VERSION 5.7 ;
  NOWIREEXTENSIONATPIN ON ;
  DIVIDERCHAR "/" ;
  BUSBITCHARS "[]" ;
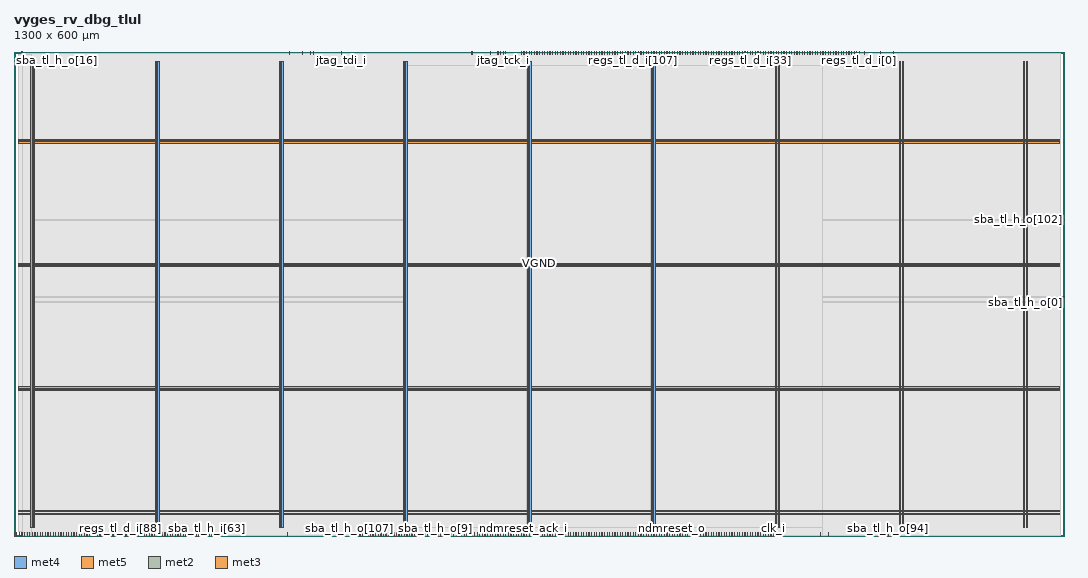
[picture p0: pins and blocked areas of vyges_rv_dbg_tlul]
MACRO vyges_rv_dbg_tlul
  CLASS BLOCK ;
  FOREIGN vyges_rv_dbg_tlul ;
  ORIGIN 0.000 0.000 ;
  SIZE 1300.000 BY 600.000 ;
  PIN VGND
    DIRECTION INOUT ;
    USE GROUND ;
    PORT
      LAYER met4 ;
        RECT 24.340 10.640 25.940 587.760 ;
    END
    PORT
      LAYER met4 ;
        RECT 177.940 10.640 179.540 587.760 ;
    END
    PORT
      LAYER met4 ;
        RECT 331.540 10.640 333.140 587.760 ;
    END
    PORT
      LAYER met4 ;
        RECT 485.140 10.640 486.740 587.760 ;
    END
    PORT
      LAYER met4 ;
        RECT 638.740 10.640 640.340 587.760 ;
    END
    PORT
      LAYER met4 ;
        RECT 792.340 10.640 793.940 587.760 ;
    END
    PORT
      LAYER met4 ;
        RECT 945.940 10.640 947.540 587.760 ;
    END
    PORT
      LAYER met4 ;
        RECT 1099.540 10.640 1101.140 587.760 ;
    END
    PORT
      LAYER met4 ;
        RECT 1253.140 10.640 1254.740 587.760 ;
    END
    PORT
      LAYER met5 ;
        RECT 5.280 30.030 1294.680 31.630 ;
    END
    PORT
      LAYER met5 ;
        RECT 5.280 183.210 1294.680 184.810 ;
    END
    PORT
      LAYER met5 ;
        RECT 5.280 336.390 1294.680 337.990 ;
    END
    PORT
      LAYER met5 ;
        RECT 5.280 489.570 1294.680 491.170 ;
    END
  END VGND
  PIN VPWR
    DIRECTION INOUT ;
    USE POWER ;
    PORT
      LAYER met4 ;
        RECT 21.040 10.640 22.640 587.760 ;
    END
    PORT
      LAYER met4 ;
        RECT 174.640 10.640 176.240 587.760 ;
    END
    PORT
      LAYER met4 ;
        RECT 328.240 10.640 329.840 587.760 ;
    END
    PORT
      LAYER met4 ;
        RECT 481.840 10.640 483.440 587.760 ;
    END
    PORT
      LAYER met4 ;
        RECT 635.440 10.640 637.040 587.760 ;
    END
    PORT
      LAYER met4 ;
        RECT 789.040 10.640 790.640 587.760 ;
    END
    PORT
      LAYER met4 ;
        RECT 942.640 10.640 944.240 587.760 ;
    END
    PORT
      LAYER met4 ;
        RECT 1096.240 10.640 1097.840 587.760 ;
    END
    PORT
      LAYER met4 ;
        RECT 1249.840 10.640 1251.440 587.760 ;
    END
    PORT
      LAYER met5 ;
        RECT 5.280 26.730 1294.680 28.330 ;
    END
    PORT
      LAYER met5 ;
        RECT 5.280 179.910 1294.680 181.510 ;
    END
    PORT
      LAYER met5 ;
        RECT 5.280 333.090 1294.680 334.690 ;
    END
    PORT
      LAYER met5 ;
        RECT 5.280 486.270 1294.680 487.870 ;
    END
  END VPWR
  PIN clk_i
    DIRECTION INPUT ;
    USE SIGNAL ;
    ANTENNAGATEAREA 1.286700 ;
    ANTENNADIFFAREA 0.434700 ;
    PORT
      LAYER met2 ;
        RECT 940.330 0.000 940.610 4.000 ;
    END
  END clk_i
  PIN debug_req_o
    DIRECTION OUTPUT ;
    USE SIGNAL ;
    ANTENNADIFFAREA 0.445500 ;
    PORT
      LAYER met2 ;
        RECT 914.570 0.000 914.850 4.000 ;
    END
  END debug_req_o
  PIN dmactive_o
    DIRECTION OUTPUT ;
    USE SIGNAL ;
    ANTENNADIFFAREA 0.445500 ;
    PORT
      LAYER met2 ;
        RECT 917.790 0.000 918.070 4.000 ;
    END
  END dmactive_o
  PIN jtag_tck_i
    DIRECTION INPUT ;
    USE SIGNAL ;
    ANTENNAGATEAREA 0.631200 ;
    ANTENNADIFFAREA 0.434700 ;
    PORT
      LAYER met2 ;
        RECT 605.450 596.000 605.730 600.000 ;
    END
  END jtag_tck_i
  PIN jtag_tdi_i
    DIRECTION INPUT ;
    USE SIGNAL ;
    ANTENNAGATEAREA 0.647700 ;
    ANTENNADIFFAREA 0.434700 ;
    PORT
      LAYER met2 ;
        RECT 405.810 596.000 406.090 600.000 ;
    END
  END jtag_tdi_i
  PIN jtag_tdo_o
    DIRECTION OUTPUT ;
    USE SIGNAL ;
    ANTENNADIFFAREA 0.445500 ;
    PORT
      LAYER met2 ;
        RECT 370.390 596.000 370.670 600.000 ;
    END
  END jtag_tdo_o
  PIN jtag_tdo_oe_o
    DIRECTION OUTPUT ;
    USE SIGNAL ;
    ANTENNADIFFAREA 0.445500 ;
    PORT
      LAYER met2 ;
        RECT 367.170 596.000 367.450 600.000 ;
    END
  END jtag_tdo_oe_o
  PIN jtag_tms_i
    DIRECTION INPUT ;
    USE SIGNAL ;
    ANTENNAGATEAREA 0.647700 ;
    ANTENNADIFFAREA 0.434700 ;
    PORT
      LAYER met2 ;
        RECT 341.410 596.000 341.690 600.000 ;
    END
  END jtag_tms_i
  PIN jtag_trst_ni
    DIRECTION INPUT ;
    USE SIGNAL ;
    ANTENNAGATEAREA 0.631200 ;
    ANTENNADIFFAREA 0.434700 ;
    PORT
      LAYER met2 ;
        RECT 602.230 596.000 602.510 600.000 ;
    END
  END jtag_trst_ni
  PIN ndmreset_ack_i
    DIRECTION INPUT ;
    USE SIGNAL ;
    ANTENNAGATEAREA 0.647700 ;
    ANTENNADIFFAREA 0.434700 ;
    PORT
      LAYER met2 ;
        RECT 631.210 0.000 631.490 4.000 ;
    END
  END ndmreset_ack_i
  PIN ndmreset_o
    DIRECTION OUTPUT ;
    USE SIGNAL ;
    ANTENNADIFFAREA 0.445500 ;
    PORT
      LAYER met2 ;
        RECT 814.750 0.000 815.030 4.000 ;
    END
  END ndmreset_o
  PIN next_dm_addr_i[0]
    DIRECTION INPUT ;
    USE SIGNAL ;
    ANTENNAGATEAREA 0.560700 ;
    ANTENNADIFFAREA 0.434700 ;
    PORT
      LAYER met2 ;
        RECT 708.490 0.000 708.770 4.000 ;
    END
  END next_dm_addr_i[0]
  PIN next_dm_addr_i[10]
    DIRECTION INPUT ;
    USE SIGNAL ;
    ANTENNAGATEAREA 0.560700 ;
    ANTENNADIFFAREA 0.434700 ;
    PORT
      LAYER met2 ;
        RECT 689.170 0.000 689.450 4.000 ;
    END
  END next_dm_addr_i[10]
  PIN next_dm_addr_i[11]
    DIRECTION INPUT ;
    USE SIGNAL ;
    ANTENNAGATEAREA 0.647700 ;
    ANTENNADIFFAREA 0.434700 ;
    PORT
      LAYER met2 ;
        RECT 753.570 0.000 753.850 4.000 ;
    END
  END next_dm_addr_i[11]
  PIN next_dm_addr_i[12]
    DIRECTION INPUT ;
    USE SIGNAL ;
    ANTENNAGATEAREA 0.560700 ;
    ANTENNADIFFAREA 0.434700 ;
    PORT
      LAYER met2 ;
        RECT 702.050 0.000 702.330 4.000 ;
    END
  END next_dm_addr_i[12]
  PIN next_dm_addr_i[13]
    DIRECTION INPUT ;
    USE SIGNAL ;
    ANTENNAGATEAREA 0.647700 ;
    ANTENNADIFFAREA 0.434700 ;
    PORT
      LAYER met2 ;
        RECT 714.930 0.000 715.210 4.000 ;
    END
  END next_dm_addr_i[13]
  PIN next_dm_addr_i[14]
    DIRECTION INPUT ;
    USE SIGNAL ;
    ANTENNAGATEAREA 0.593700 ;
    ANTENNADIFFAREA 0.434700 ;
    PORT
      LAYER met2 ;
        RECT 627.990 596.000 628.270 600.000 ;
    END
  END next_dm_addr_i[14]
  PIN next_dm_addr_i[15]
    DIRECTION INPUT ;
    USE SIGNAL ;
    ANTENNAGATEAREA 0.647700 ;
    ANTENNADIFFAREA 0.434700 ;
    PORT
      LAYER met2 ;
        RECT 599.010 596.000 599.290 600.000 ;
    END
  END next_dm_addr_i[15]
  PIN next_dm_addr_i[16]
    DIRECTION INPUT ;
    USE SIGNAL ;
    ANTENNAGATEAREA 0.631200 ;
    ANTENNADIFFAREA 0.434700 ;
    PORT
      LAYER met2 ;
        RECT 695.610 0.000 695.890 4.000 ;
    END
  END next_dm_addr_i[16]
  PIN next_dm_addr_i[17]
    DIRECTION INPUT ;
    USE SIGNAL ;
    ANTENNAGATEAREA 0.631200 ;
    ANTENNADIFFAREA 0.434700 ;
    PORT
      LAYER met2 ;
        RECT 669.850 0.000 670.130 4.000 ;
    END
  END next_dm_addr_i[17]
  PIN next_dm_addr_i[18]
    DIRECTION INPUT ;
    USE SIGNAL ;
    ANTENNAGATEAREA 0.593700 ;
    ANTENNADIFFAREA 0.434700 ;
    PORT
      LAYER met2 ;
        RECT 937.110 0.000 937.390 4.000 ;
    END
  END next_dm_addr_i[18]
  PIN next_dm_addr_i[19]
    DIRECTION INPUT ;
    USE SIGNAL ;
    ANTENNAGATEAREA 0.647700 ;
    ANTENNADIFFAREA 0.434700 ;
    PORT
      LAYER met2 ;
        RECT 637.650 0.000 637.930 4.000 ;
    END
  END next_dm_addr_i[19]
  PIN next_dm_addr_i[1]
    DIRECTION INPUT ;
    USE SIGNAL ;
    ANTENNAGATEAREA 0.560700 ;
    ANTENNADIFFAREA 0.434700 ;
    PORT
      LAYER met2 ;
        RECT 769.670 0.000 769.950 4.000 ;
    END
  END next_dm_addr_i[1]
  PIN next_dm_addr_i[20]
    DIRECTION INPUT ;
    USE SIGNAL ;
    ANTENNAGATEAREA 0.647700 ;
    ANTENNADIFFAREA 0.434700 ;
    PORT
      LAYER met2 ;
        RECT 599.010 0.000 599.290 4.000 ;
    END
  END next_dm_addr_i[20]
  PIN next_dm_addr_i[21]
    DIRECTION INPUT ;
    USE SIGNAL ;
    ANTENNAGATEAREA 0.647700 ;
    ANTENNADIFFAREA 0.434700 ;
    PORT
      LAYER met2 ;
        RECT 627.990 0.000 628.270 4.000 ;
    END
  END next_dm_addr_i[21]
  PIN next_dm_addr_i[22]
    DIRECTION INPUT ;
    USE SIGNAL ;
    ANTENNAGATEAREA 0.647700 ;
    ANTENNADIFFAREA 0.434700 ;
    PORT
      LAYER met2 ;
        RECT 624.770 0.000 625.050 4.000 ;
    END
  END next_dm_addr_i[22]
  PIN next_dm_addr_i[23]
    DIRECTION INPUT ;
    USE SIGNAL ;
    ANTENNAGATEAREA 0.647700 ;
    ANTENNADIFFAREA 0.434700 ;
    PORT
      LAYER met2 ;
        RECT 621.550 0.000 621.830 4.000 ;
    END
  END next_dm_addr_i[23]
  PIN next_dm_addr_i[24]
    DIRECTION INPUT ;
    USE SIGNAL ;
    ANTENNAGATEAREA 0.647700 ;
    ANTENNADIFFAREA 0.434700 ;
    PORT
      LAYER met2 ;
        RECT 573.250 0.000 573.530 4.000 ;
    END
  END next_dm_addr_i[24]
  PIN next_dm_addr_i[25]
    DIRECTION INPUT ;
    USE SIGNAL ;
    ANTENNAGATEAREA 0.560700 ;
    ANTENNADIFFAREA 0.434700 ;
    PORT
      LAYER met2 ;
        RECT 776.110 0.000 776.390 4.000 ;
    END
  END next_dm_addr_i[25]
  PIN next_dm_addr_i[26]
    DIRECTION INPUT ;
    USE SIGNAL ;
    ANTENNAGATEAREA 0.560700 ;
    ANTENNADIFFAREA 0.434700 ;
    PORT
      LAYER met2 ;
        RECT 801.870 0.000 802.150 4.000 ;
    END
  END next_dm_addr_i[26]
  PIN next_dm_addr_i[27]
    DIRECTION INPUT ;
    USE SIGNAL ;
    ANTENNAGATEAREA 0.647700 ;
    ANTENNADIFFAREA 0.434700 ;
    PORT
      LAYER met2 ;
        RECT 592.570 0.000 592.850 4.000 ;
    END
  END next_dm_addr_i[27]
  PIN next_dm_addr_i[28]
    DIRECTION INPUT ;
    USE SIGNAL ;
    ANTENNAGATEAREA 0.647700 ;
    ANTENNADIFFAREA 0.434700 ;
    PORT
      LAYER met2 ;
        RECT 582.910 0.000 583.190 4.000 ;
    END
  END next_dm_addr_i[28]
  PIN next_dm_addr_i[29]
    DIRECTION INPUT ;
    USE SIGNAL ;
    ANTENNAGATEAREA 0.647700 ;
    ANTENNADIFFAREA 0.434700 ;
    PORT
      LAYER met2 ;
        RECT 644.090 0.000 644.370 4.000 ;
    END
  END next_dm_addr_i[29]
  PIN next_dm_addr_i[2]
    DIRECTION INPUT ;
    USE SIGNAL ;
    ANTENNAGATEAREA 0.647700 ;
    ANTENNADIFFAREA 0.434700 ;
    PORT
      LAYER met2 ;
        RECT 856.610 0.000 856.890 4.000 ;
    END
  END next_dm_addr_i[2]
  PIN next_dm_addr_i[30]
    DIRECTION INPUT ;
    USE SIGNAL ;
    ANTENNAGATEAREA 0.560700 ;
    ANTENNADIFFAREA 0.434700 ;
    PORT
      LAYER met2 ;
        RECT 705.270 0.000 705.550 4.000 ;
    END
  END next_dm_addr_i[30]
  PIN next_dm_addr_i[31]
    DIRECTION INPUT ;
    USE SIGNAL ;
    ANTENNAGATEAREA 0.647700 ;
    ANTENNADIFFAREA 0.434700 ;
    PORT
      LAYER met2 ;
        RECT 666.630 0.000 666.910 4.000 ;
    END
  END next_dm_addr_i[31]
  PIN next_dm_addr_i[3]
    DIRECTION INPUT ;
    USE SIGNAL ;
    ANTENNAGATEAREA 0.593700 ;
    ANTENNADIFFAREA 0.434700 ;
    PORT
      LAYER met2 ;
        RECT 589.350 596.000 589.630 600.000 ;
    END
  END next_dm_addr_i[3]
  PIN next_dm_addr_i[4]
    DIRECTION INPUT ;
    USE SIGNAL ;
    ANTENNAGATEAREA 0.593700 ;
    ANTENNADIFFAREA 0.434700 ;
    PORT
      LAYER met2 ;
        RECT 647.310 596.000 647.590 600.000 ;
    END
  END next_dm_addr_i[4]
  PIN next_dm_addr_i[5]
    DIRECTION INPUT ;
    USE SIGNAL ;
    ANTENNAGATEAREA 0.631200 ;
    ANTENNADIFFAREA 0.434700 ;
    PORT
      LAYER met2 ;
        RECT 805.090 0.000 805.370 4.000 ;
    END
  END next_dm_addr_i[5]
  PIN next_dm_addr_i[6]
    DIRECTION INPUT ;
    USE SIGNAL ;
    ANTENNAGATEAREA 0.647700 ;
    ANTENNADIFFAREA 0.434700 ;
    PORT
      LAYER met2 ;
        RECT 608.670 0.000 608.950 4.000 ;
    END
  END next_dm_addr_i[6]
  PIN next_dm_addr_i[7]
    DIRECTION INPUT ;
    USE SIGNAL ;
    ANTENNAGATEAREA 0.647700 ;
    ANTENNADIFFAREA 0.434700 ;
    PORT
      LAYER met2 ;
        RECT 653.750 0.000 654.030 4.000 ;
    END
  END next_dm_addr_i[7]
  PIN next_dm_addr_i[8]
    DIRECTION INPUT ;
    USE SIGNAL ;
    ANTENNAGATEAREA 0.631200 ;
    ANTENNADIFFAREA 0.434700 ;
    PORT
      LAYER met2 ;
        RECT 727.810 0.000 728.090 4.000 ;
    END
  END next_dm_addr_i[8]
  PIN next_dm_addr_i[9]
    DIRECTION INPUT ;
    USE SIGNAL ;
    ANTENNAGATEAREA 0.593700 ;
    ANTENNADIFFAREA 0.434700 ;
    PORT
      LAYER met2 ;
        RECT 924.230 0.000 924.510 4.000 ;
    END
  END next_dm_addr_i[9]
  PIN regs_tl_d_i[0]
    DIRECTION INPUT ;
    USE SIGNAL ;
    ANTENNAGATEAREA 0.560700 ;
    ANTENNADIFFAREA 0.434700 ;
    PORT
      LAYER met2 ;
        RECT 1046.590 596.000 1046.870 600.000 ;
    END
  END regs_tl_d_i[0]
  PIN regs_tl_d_i[100]
    DIRECTION INPUT ;
    USE SIGNAL ;
    ANTENNAGATEAREA 0.647700 ;
    ANTENNADIFFAREA 0.434700 ;
    PORT
      LAYER met2 ;
        RECT 978.970 596.000 979.250 600.000 ;
    END
  END regs_tl_d_i[100]
  PIN regs_tl_d_i[101]
    DIRECTION INPUT ;
    USE SIGNAL ;
    ANTENNAGATEAREA 0.631200 ;
    ANTENNADIFFAREA 0.434700 ;
    PORT
      LAYER met2 ;
        RECT 689.170 596.000 689.450 600.000 ;
    END
  END regs_tl_d_i[101]
  PIN regs_tl_d_i[102]
    DIRECTION INPUT ;
    USE SIGNAL ;
    ANTENNAGATEAREA 0.631200 ;
    ANTENNADIFFAREA 0.434700 ;
    PORT
      LAYER met2 ;
        RECT 656.970 596.000 657.250 600.000 ;
    END
  END regs_tl_d_i[102]
  PIN regs_tl_d_i[103]
    DIRECTION INPUT ;
    USE SIGNAL ;
    PORT
      LAYER met2 ;
        RECT 0.090 0.000 0.370 4.000 ;
    END
  END regs_tl_d_i[103]
  PIN regs_tl_d_i[104]
    DIRECTION INPUT ;
    USE SIGNAL ;
    PORT
      LAYER met2 ;
        RECT 3.310 0.000 3.590 4.000 ;
    END
  END regs_tl_d_i[104]
  PIN regs_tl_d_i[105]
    DIRECTION INPUT ;
    USE SIGNAL ;
    PORT
      LAYER met2 ;
        RECT 6.530 0.000 6.810 4.000 ;
    END
  END regs_tl_d_i[105]
  PIN regs_tl_d_i[106]
    DIRECTION INPUT ;
    USE SIGNAL ;
    PORT
      LAYER met2 ;
        RECT 9.750 0.000 10.030 4.000 ;
    END
  END regs_tl_d_i[106]
  PIN regs_tl_d_i[107]
    DIRECTION INPUT ;
    USE SIGNAL ;
    ANTENNAGATEAREA 0.631200 ;
    ANTENNADIFFAREA 0.434700 ;
    PORT
      LAYER met2 ;
        RECT 766.450 596.000 766.730 600.000 ;
    END
  END regs_tl_d_i[107]
  PIN regs_tl_d_i[108]
    DIRECTION INPUT ;
    USE SIGNAL ;
    ANTENNAGATEAREA 0.631200 ;
    ANTENNADIFFAREA 0.434700 ;
    PORT
      LAYER met2 ;
        RECT 763.230 596.000 763.510 600.000 ;
    END
  END regs_tl_d_i[108]
  PIN regs_tl_d_i[109]
    DIRECTION INPUT ;
    USE SIGNAL ;
    ANTENNAGATEAREA 0.631200 ;
    ANTENNADIFFAREA 0.434700 ;
    PORT
      LAYER met2 ;
        RECT 917.790 596.000 918.070 600.000 ;
    END
  END regs_tl_d_i[109]
  PIN regs_tl_d_i[10]
    DIRECTION INPUT ;
    USE SIGNAL ;
    PORT
      LAYER met2 ;
        RECT 12.970 0.000 13.250 4.000 ;
    END
  END regs_tl_d_i[10]
  PIN regs_tl_d_i[11]
    DIRECTION INPUT ;
    USE SIGNAL ;
    PORT
      LAYER met2 ;
        RECT 16.190 0.000 16.470 4.000 ;
    END
  END regs_tl_d_i[11]
  PIN regs_tl_d_i[12]
    DIRECTION INPUT ;
    USE SIGNAL ;
    PORT
      LAYER met2 ;
        RECT 19.410 0.000 19.690 4.000 ;
    END
  END regs_tl_d_i[12]
  PIN regs_tl_d_i[13]
    DIRECTION INPUT ;
    USE SIGNAL ;
    PORT
      LAYER met2 ;
        RECT 22.630 0.000 22.910 4.000 ;
    END
  END regs_tl_d_i[13]
  PIN regs_tl_d_i[14]
    DIRECTION INPUT ;
    USE SIGNAL ;
    PORT
      LAYER met2 ;
        RECT 25.850 0.000 26.130 4.000 ;
    END
  END regs_tl_d_i[14]
  PIN regs_tl_d_i[15]
    DIRECTION INPUT ;
    USE SIGNAL ;
    PORT
      LAYER met2 ;
        RECT 29.070 0.000 29.350 4.000 ;
    END
  END regs_tl_d_i[15]
  PIN regs_tl_d_i[16]
    DIRECTION INPUT ;
    USE SIGNAL ;
    PORT
      LAYER met2 ;
        RECT 32.290 0.000 32.570 4.000 ;
    END
  END regs_tl_d_i[16]
  PIN regs_tl_d_i[17]
    DIRECTION INPUT ;
    USE SIGNAL ;
    PORT
      LAYER met2 ;
        RECT 35.510 0.000 35.790 4.000 ;
    END
  END regs_tl_d_i[17]
  PIN regs_tl_d_i[18]
    DIRECTION INPUT ;
    USE SIGNAL ;
    PORT
      LAYER met2 ;
        RECT 38.730 0.000 39.010 4.000 ;
    END
  END regs_tl_d_i[18]
  PIN regs_tl_d_i[19]
    DIRECTION INPUT ;
    USE SIGNAL ;
    PORT
      LAYER met2 ;
        RECT 41.950 0.000 42.230 4.000 ;
    END
  END regs_tl_d_i[19]
  PIN regs_tl_d_i[1]
    DIRECTION INPUT ;
    USE SIGNAL ;
    PORT
      LAYER met2 ;
        RECT 45.170 0.000 45.450 4.000 ;
    END
  END regs_tl_d_i[1]
  PIN regs_tl_d_i[20]
    DIRECTION INPUT ;
    USE SIGNAL ;
    PORT
      LAYER met2 ;
        RECT 48.390 0.000 48.670 4.000 ;
    END
  END regs_tl_d_i[20]
  PIN regs_tl_d_i[21]
    DIRECTION INPUT ;
    USE SIGNAL ;
    PORT
      LAYER met2 ;
        RECT 51.610 0.000 51.890 4.000 ;
    END
  END regs_tl_d_i[21]
  PIN regs_tl_d_i[22]
    DIRECTION INPUT ;
    USE SIGNAL ;
    PORT
      LAYER met2 ;
        RECT 54.830 0.000 55.110 4.000 ;
    END
  END regs_tl_d_i[22]
  PIN regs_tl_d_i[23]
    DIRECTION INPUT ;
    USE SIGNAL ;
    PORT
      LAYER met2 ;
        RECT 58.050 0.000 58.330 4.000 ;
    END
  END regs_tl_d_i[23]
  PIN regs_tl_d_i[24]
    DIRECTION INPUT ;
    USE SIGNAL ;
    PORT
      LAYER met2 ;
        RECT 61.270 0.000 61.550 4.000 ;
    END
  END regs_tl_d_i[24]
  PIN regs_tl_d_i[25]
    DIRECTION INPUT ;
    USE SIGNAL ;
    ANTENNAGATEAREA 0.631200 ;
    ANTENNADIFFAREA 0.434700 ;
    PORT
      LAYER met2 ;
        RECT 760.010 596.000 760.290 600.000 ;
    END
  END regs_tl_d_i[25]
  PIN regs_tl_d_i[26]
    DIRECTION INPUT ;
    USE SIGNAL ;
    ANTENNAGATEAREA 0.631200 ;
    ANTENNADIFFAREA 0.434700 ;
    PORT
      LAYER met2 ;
        RECT 1001.510 596.000 1001.790 600.000 ;
    END
  END regs_tl_d_i[26]
  PIN regs_tl_d_i[27]
    DIRECTION INPUT ;
    USE SIGNAL ;
    ANTENNAGATEAREA 0.560700 ;
    ANTENNADIFFAREA 0.434700 ;
    PORT
      LAYER met2 ;
        RECT 998.290 596.000 998.570 600.000 ;
    END
  END regs_tl_d_i[27]
  PIN regs_tl_d_i[28]
    DIRECTION INPUT ;
    USE SIGNAL ;
    ANTENNAGATEAREA 0.631200 ;
    ANTENNADIFFAREA 0.434700 ;
    PORT
      LAYER met2 ;
        RECT 660.190 596.000 660.470 600.000 ;
    END
  END regs_tl_d_i[28]
  PIN regs_tl_d_i[29]
    DIRECTION INPUT ;
    USE SIGNAL ;
    ANTENNAGATEAREA 0.560700 ;
    ANTENNADIFFAREA 0.434700 ;
    PORT
      LAYER met2 ;
        RECT 1036.930 596.000 1037.210 600.000 ;
    END
  END regs_tl_d_i[29]
  PIN regs_tl_d_i[2]
    DIRECTION INPUT ;
    USE SIGNAL ;
    PORT
      LAYER met2 ;
        RECT 64.490 0.000 64.770 4.000 ;
    END
  END regs_tl_d_i[2]
  PIN regs_tl_d_i[30]
    DIRECTION INPUT ;
    USE SIGNAL ;
    ANTENNAGATEAREA 0.631200 ;
    ANTENNADIFFAREA 0.434700 ;
    PORT
      LAYER met2 ;
        RECT 747.130 596.000 747.410 600.000 ;
    END
  END regs_tl_d_i[30]
  PIN regs_tl_d_i[31]
    DIRECTION INPUT ;
    USE SIGNAL ;
    ANTENNAGATEAREA 0.560700 ;
    ANTENNADIFFAREA 0.434700 ;
    PORT
      LAYER met2 ;
        RECT 1030.490 596.000 1030.770 600.000 ;
    END
  END regs_tl_d_i[31]
  PIN regs_tl_d_i[32]
    DIRECTION INPUT ;
    USE SIGNAL ;
    ANTENNAGATEAREA 0.631200 ;
    ANTENNADIFFAREA 0.434700 ;
    PORT
      LAYER met2 ;
        RECT 663.410 596.000 663.690 600.000 ;
    END
  END regs_tl_d_i[32]
  PIN regs_tl_d_i[33]
    DIRECTION INPUT ;
    USE SIGNAL ;
    ANTENNAGATEAREA 0.631200 ;
    ANTENNADIFFAREA 0.434700 ;
    PORT
      LAYER met2 ;
        RECT 911.350 596.000 911.630 600.000 ;
    END
  END regs_tl_d_i[33]
  PIN regs_tl_d_i[34]
    DIRECTION INPUT ;
    USE SIGNAL ;
    ANTENNAGATEAREA 0.631200 ;
    ANTENNADIFFAREA 0.434700 ;
    PORT
      LAYER met2 ;
        RECT 924.230 596.000 924.510 600.000 ;
    END
  END regs_tl_d_i[34]
  PIN regs_tl_d_i[35]
    DIRECTION INPUT ;
    USE SIGNAL ;
    ANTENNAGATEAREA 0.631200 ;
    ANTENNADIFFAREA 0.434700 ;
    PORT
      LAYER met2 ;
        RECT 953.210 596.000 953.490 600.000 ;
    END
  END regs_tl_d_i[35]
  PIN regs_tl_d_i[36]
    DIRECTION INPUT ;
    USE SIGNAL ;
    ANTENNAGATEAREA 0.631200 ;
    ANTENNADIFFAREA 0.434700 ;
    PORT
      LAYER met2 ;
        RECT 921.010 596.000 921.290 600.000 ;
    END
  END regs_tl_d_i[36]
  PIN regs_tl_d_i[37]
    DIRECTION INPUT ;
    USE SIGNAL ;
    ANTENNAGATEAREA 0.631200 ;
    ANTENNADIFFAREA 0.434700 ;
    PORT
      LAYER met2 ;
        RECT 901.690 596.000 901.970 600.000 ;
    END
  END regs_tl_d_i[37]
  PIN regs_tl_d_i[38]
    DIRECTION INPUT ;
    USE SIGNAL ;
    ANTENNAGATEAREA 0.631200 ;
    ANTENNADIFFAREA 0.434700 ;
    PORT
      LAYER met2 ;
        RECT 827.630 596.000 827.910 600.000 ;
    END
  END regs_tl_d_i[38]
  PIN regs_tl_d_i[39]
    DIRECTION INPUT ;
    USE SIGNAL ;
    ANTENNAGATEAREA 0.631200 ;
    ANTENNADIFFAREA 0.434700 ;
    PORT
      LAYER met2 ;
        RECT 1027.270 596.000 1027.550 600.000 ;
    END
  END regs_tl_d_i[39]
  PIN regs_tl_d_i[3]
    DIRECTION INPUT ;
    USE SIGNAL ;
    PORT
      LAYER met2 ;
        RECT 67.710 0.000 67.990 4.000 ;
    END
  END regs_tl_d_i[3]
  PIN regs_tl_d_i[40]
    DIRECTION INPUT ;
    USE SIGNAL ;
    ANTENNAGATEAREA 0.631200 ;
    ANTENNADIFFAREA 0.434700 ;
    PORT
      LAYER met2 ;
        RECT 685.950 596.000 686.230 600.000 ;
    END
  END regs_tl_d_i[40]
  PIN regs_tl_d_i[41]
    DIRECTION INPUT ;
    USE SIGNAL ;
    ANTENNAGATEAREA 0.631200 ;
    ANTENNADIFFAREA 0.434700 ;
    PORT
      LAYER met2 ;
        RECT 702.050 596.000 702.330 600.000 ;
    END
  END regs_tl_d_i[41]
  PIN regs_tl_d_i[42]
    DIRECTION INPUT ;
    USE SIGNAL ;
    ANTENNAGATEAREA 0.631200 ;
    ANTENNADIFFAREA 0.434700 ;
    PORT
      LAYER met2 ;
        RECT 631.210 596.000 631.490 600.000 ;
    END
  END regs_tl_d_i[42]
  PIN regs_tl_d_i[43]
    DIRECTION INPUT ;
    USE SIGNAL ;
    ANTENNAGATEAREA 0.631200 ;
    ANTENNADIFFAREA 0.434700 ;
    PORT
      LAYER met2 ;
        RECT 975.750 596.000 976.030 600.000 ;
    END
  END regs_tl_d_i[43]
  PIN regs_tl_d_i[44]
    DIRECTION INPUT ;
    USE SIGNAL ;
    ANTENNAGATEAREA 0.631200 ;
    ANTENNADIFFAREA 0.434700 ;
    PORT
      LAYER met2 ;
        RECT 650.530 596.000 650.810 600.000 ;
    END
  END regs_tl_d_i[44]
  PIN regs_tl_d_i[45]
    DIRECTION INPUT ;
    USE SIGNAL ;
    ANTENNAGATEAREA 0.631200 ;
    ANTENNADIFFAREA 0.434700 ;
    PORT
      LAYER met2 ;
        RECT 985.410 596.000 985.690 600.000 ;
    END
  END regs_tl_d_i[45]
  PIN regs_tl_d_i[46]
    DIRECTION INPUT ;
    USE SIGNAL ;
    ANTENNAGATEAREA 0.631200 ;
    ANTENNADIFFAREA 0.434700 ;
    PORT
      LAYER met2 ;
        RECT 779.330 596.000 779.610 600.000 ;
    END
  END regs_tl_d_i[46]
  PIN regs_tl_d_i[47]
    DIRECTION INPUT ;
    USE SIGNAL ;
    ANTENNAGATEAREA 0.631200 ;
    ANTENNADIFFAREA 0.434700 ;
    PORT
      LAYER met2 ;
        RECT 769.670 596.000 769.950 600.000 ;
    END
  END regs_tl_d_i[47]
  PIN regs_tl_d_i[48]
    DIRECTION INPUT ;
    USE SIGNAL ;
    ANTENNAGATEAREA 0.631200 ;
    ANTENNADIFFAREA 0.434700 ;
    PORT
      LAYER met2 ;
        RECT 743.910 596.000 744.190 600.000 ;
    END
  END regs_tl_d_i[48]
  PIN regs_tl_d_i[49]
    DIRECTION INPUT ;
    USE SIGNAL ;
    ANTENNAGATEAREA 0.631200 ;
    ANTENNADIFFAREA 0.434700 ;
    PORT
      LAYER met2 ;
        RECT 653.750 596.000 654.030 600.000 ;
    END
  END regs_tl_d_i[49]
  PIN regs_tl_d_i[4]
    DIRECTION INPUT ;
    USE SIGNAL ;
    PORT
      LAYER met2 ;
        RECT 70.930 0.000 71.210 4.000 ;
    END
  END regs_tl_d_i[4]
  PIN regs_tl_d_i[50]
    DIRECTION INPUT ;
    USE SIGNAL ;
    ANTENNAGATEAREA 0.631200 ;
    ANTENNADIFFAREA 0.434700 ;
    PORT
      LAYER met2 ;
        RECT 1011.170 596.000 1011.450 600.000 ;
    END
  END regs_tl_d_i[50]
  PIN regs_tl_d_i[51]
    DIRECTION INPUT ;
    USE SIGNAL ;
    ANTENNAGATEAREA 0.631200 ;
    ANTENNADIFFAREA 0.434700 ;
    PORT
      LAYER met2 ;
        RECT 1014.390 596.000 1014.670 600.000 ;
    END
  END regs_tl_d_i[51]
  PIN regs_tl_d_i[52]
    DIRECTION INPUT ;
    USE SIGNAL ;
    ANTENNAGATEAREA 0.631200 ;
    ANTENNADIFFAREA 0.434700 ;
    PORT
      LAYER met2 ;
        RECT 640.870 596.000 641.150 600.000 ;
    END
  END regs_tl_d_i[52]
  PIN regs_tl_d_i[53]
    DIRECTION INPUT ;
    USE SIGNAL ;
    ANTENNAGATEAREA 0.631200 ;
    ANTENNADIFFAREA 0.434700 ;
    PORT
      LAYER met2 ;
        RECT 634.430 596.000 634.710 600.000 ;
    END
  END regs_tl_d_i[53]
  PIN regs_tl_d_i[54]
    DIRECTION INPUT ;
    USE SIGNAL ;
    ANTENNAGATEAREA 0.631200 ;
    ANTENNADIFFAREA 0.434700 ;
    PORT
      LAYER met2 ;
        RECT 644.090 596.000 644.370 600.000 ;
    END
  END regs_tl_d_i[54]
  PIN regs_tl_d_i[55]
    DIRECTION INPUT ;
    USE SIGNAL ;
    ANTENNAGATEAREA 0.631200 ;
    ANTENNADIFFAREA 0.434700 ;
    PORT
      LAYER met2 ;
        RECT 676.290 596.000 676.570 600.000 ;
    END
  END regs_tl_d_i[55]
  PIN regs_tl_d_i[56]
    DIRECTION INPUT ;
    USE SIGNAL ;
    ANTENNAGATEAREA 0.631200 ;
    ANTENNADIFFAREA 0.434700 ;
    PORT
      LAYER met2 ;
        RECT 698.830 596.000 699.110 600.000 ;
    END
  END regs_tl_d_i[56]
  PIN regs_tl_d_i[57]
    DIRECTION INPUT ;
    USE SIGNAL ;
    ANTENNAGATEAREA 0.631200 ;
    ANTENNADIFFAREA 0.434700 ;
    PORT
      LAYER met2 ;
        RECT 1017.610 596.000 1017.890 600.000 ;
    END
  END regs_tl_d_i[57]
  PIN regs_tl_d_i[58]
    DIRECTION INPUT ;
    USE SIGNAL ;
    ANTENNAGATEAREA 0.631200 ;
    ANTENNADIFFAREA 0.434700 ;
    PORT
      LAYER met2 ;
        RECT 711.710 596.000 711.990 600.000 ;
    END
  END regs_tl_d_i[58]
  PIN regs_tl_d_i[59]
    DIRECTION INPUT ;
    USE SIGNAL ;
    ANTENNAGATEAREA 0.631200 ;
    ANTENNADIFFAREA 0.434700 ;
    PORT
      LAYER met2 ;
        RECT 1007.950 596.000 1008.230 600.000 ;
    END
  END regs_tl_d_i[59]
  PIN regs_tl_d_i[5]
    DIRECTION INPUT ;
    USE SIGNAL ;
    PORT
      LAYER met2 ;
        RECT 74.150 0.000 74.430 4.000 ;
    END
  END regs_tl_d_i[5]
  PIN regs_tl_d_i[60]
    DIRECTION INPUT ;
    USE SIGNAL ;
    ANTENNAGATEAREA 0.647700 ;
    ANTENNADIFFAREA 0.434700 ;
    PORT
      LAYER met2 ;
        RECT 1024.050 596.000 1024.330 600.000 ;
    END
  END regs_tl_d_i[60]
  PIN regs_tl_d_i[61]
    DIRECTION INPUT ;
    USE SIGNAL ;
    ANTENNAGATEAREA 0.631200 ;
    ANTENNADIFFAREA 0.434700 ;
    PORT
      LAYER met2 ;
        RECT 734.250 596.000 734.530 600.000 ;
    END
  END regs_tl_d_i[61]
  PIN regs_tl_d_i[62]
    DIRECTION INPUT ;
    USE SIGNAL ;
    ANTENNAGATEAREA 0.631200 ;
    ANTENNADIFFAREA 0.434700 ;
    PORT
      LAYER met2 ;
        RECT 988.630 596.000 988.910 600.000 ;
    END
  END regs_tl_d_i[62]
  PIN regs_tl_d_i[63]
    DIRECTION INPUT ;
    USE SIGNAL ;
    ANTENNAGATEAREA 0.631200 ;
    ANTENNADIFFAREA 0.434700 ;
    PORT
      LAYER met2 ;
        RECT 753.570 596.000 753.850 600.000 ;
    END
  END regs_tl_d_i[63]
  PIN regs_tl_d_i[64]
    DIRECTION INPUT ;
    USE SIGNAL ;
    ANTENNAGATEAREA 0.631200 ;
    ANTENNADIFFAREA 0.434700 ;
    PORT
      LAYER met2 ;
        RECT 927.450 596.000 927.730 600.000 ;
    END
  END regs_tl_d_i[64]
  PIN regs_tl_d_i[65]
    DIRECTION INPUT ;
    USE SIGNAL ;
    ANTENNAGATEAREA 0.631200 ;
    ANTENNADIFFAREA 0.434700 ;
    PORT
      LAYER met2 ;
        RECT 637.650 596.000 637.930 600.000 ;
    END
  END regs_tl_d_i[65]
  PIN regs_tl_d_i[66]
    DIRECTION INPUT ;
    USE SIGNAL ;
    ANTENNAGATEAREA 0.631200 ;
    ANTENNADIFFAREA 0.434700 ;
    PORT
      LAYER met2 ;
        RECT 940.330 596.000 940.610 600.000 ;
    END
  END regs_tl_d_i[66]
  PIN regs_tl_d_i[67]
    DIRECTION INPUT ;
    USE SIGNAL ;
    ANTENNAGATEAREA 0.631200 ;
    ANTENNADIFFAREA 0.434700 ;
    PORT
      LAYER met2 ;
        RECT 933.890 596.000 934.170 600.000 ;
    END
  END regs_tl_d_i[67]
  PIN regs_tl_d_i[68]
    DIRECTION INPUT ;
    USE SIGNAL ;
    ANTENNAGATEAREA 0.631200 ;
    ANTENNADIFFAREA 0.434700 ;
    PORT
      LAYER met2 ;
        RECT 962.870 596.000 963.150 600.000 ;
    END
  END regs_tl_d_i[68]
  PIN regs_tl_d_i[69]
    DIRECTION INPUT ;
    USE SIGNAL ;
    ANTENNAGATEAREA 0.631200 ;
    ANTENNADIFFAREA 0.434700 ;
    PORT
      LAYER met2 ;
        RECT 772.890 596.000 773.170 600.000 ;
    END
  END regs_tl_d_i[69]
  PIN regs_tl_d_i[6]
    DIRECTION INPUT ;
    USE SIGNAL ;
    PORT
      LAYER met2 ;
        RECT 77.370 0.000 77.650 4.000 ;
    END
  END regs_tl_d_i[6]
  PIN regs_tl_d_i[70]
    DIRECTION INPUT ;
    USE SIGNAL ;
    ANTENNAGATEAREA 0.631200 ;
    ANTENNADIFFAREA 0.434700 ;
    PORT
      LAYER met2 ;
        RECT 756.790 596.000 757.070 600.000 ;
    END
  END regs_tl_d_i[70]
  PIN regs_tl_d_i[71]
    DIRECTION INPUT ;
    USE SIGNAL ;
    ANTENNAGATEAREA 0.631200 ;
    ANTENNADIFFAREA 0.434700 ;
    PORT
      LAYER met2 ;
        RECT 966.090 596.000 966.370 600.000 ;
    END
  END regs_tl_d_i[71]
  PIN regs_tl_d_i[72]
    DIRECTION INPUT ;
    USE SIGNAL ;
    ANTENNAGATEAREA 0.631200 ;
    ANTENNADIFFAREA 0.434700 ;
    PORT
      LAYER met2 ;
        RECT 959.650 596.000 959.930 600.000 ;
    END
  END regs_tl_d_i[72]
  PIN regs_tl_d_i[73]
    DIRECTION INPUT ;
    USE SIGNAL ;
    PORT
      LAYER met2 ;
        RECT 80.590 0.000 80.870 4.000 ;
    END
  END regs_tl_d_i[73]
  PIN regs_tl_d_i[74]
    DIRECTION INPUT ;
    USE SIGNAL ;
    PORT
      LAYER met2 ;
        RECT 83.810 0.000 84.090 4.000 ;
    END
  END regs_tl_d_i[74]
  PIN regs_tl_d_i[75]
    DIRECTION INPUT ;
    USE SIGNAL ;
    PORT
      LAYER met2 ;
        RECT 87.030 0.000 87.310 4.000 ;
    END
  END regs_tl_d_i[75]
  PIN regs_tl_d_i[76]
    DIRECTION INPUT ;
    USE SIGNAL ;
    PORT
      LAYER met2 ;
        RECT 90.250 0.000 90.530 4.000 ;
    END
  END regs_tl_d_i[76]
  PIN regs_tl_d_i[77]
    DIRECTION INPUT ;
    USE SIGNAL ;
    PORT
      LAYER met2 ;
        RECT 93.470 0.000 93.750 4.000 ;
    END
  END regs_tl_d_i[77]
  PIN regs_tl_d_i[78]
    DIRECTION INPUT ;
    USE SIGNAL ;
    PORT
      LAYER met2 ;
        RECT 96.690 0.000 96.970 4.000 ;
    END
  END regs_tl_d_i[78]
  PIN regs_tl_d_i[79]
    DIRECTION INPUT ;
    USE SIGNAL ;
    PORT
      LAYER met2 ;
        RECT 99.910 0.000 100.190 4.000 ;
    END
  END regs_tl_d_i[79]
  PIN regs_tl_d_i[7]
    DIRECTION INPUT ;
    USE SIGNAL ;
    PORT
      LAYER met2 ;
        RECT 103.130 0.000 103.410 4.000 ;
    END
  END regs_tl_d_i[7]
  PIN regs_tl_d_i[80]
    DIRECTION INPUT ;
    USE SIGNAL ;
    PORT
      LAYER met2 ;
        RECT 106.350 0.000 106.630 4.000 ;
    END
  END regs_tl_d_i[80]
  PIN regs_tl_d_i[81]
    DIRECTION INPUT ;
    USE SIGNAL ;
    PORT
      LAYER met2 ;
        RECT 109.570 0.000 109.850 4.000 ;
    END
  END regs_tl_d_i[81]
  PIN regs_tl_d_i[82]
    DIRECTION INPUT ;
    USE SIGNAL ;
    PORT
      LAYER met2 ;
        RECT 112.790 0.000 113.070 4.000 ;
    END
  END regs_tl_d_i[82]
  PIN regs_tl_d_i[83]
    DIRECTION INPUT ;
    USE SIGNAL ;
    PORT
      LAYER met2 ;
        RECT 116.010 0.000 116.290 4.000 ;
    END
  END regs_tl_d_i[83]
  PIN regs_tl_d_i[84]
    DIRECTION INPUT ;
    USE SIGNAL ;
    PORT
      LAYER met2 ;
        RECT 119.230 0.000 119.510 4.000 ;
    END
  END regs_tl_d_i[84]
  PIN regs_tl_d_i[85]
    DIRECTION INPUT ;
    USE SIGNAL ;
    PORT
      LAYER met2 ;
        RECT 122.450 0.000 122.730 4.000 ;
    END
  END regs_tl_d_i[85]
  PIN regs_tl_d_i[86]
    DIRECTION INPUT ;
    USE SIGNAL ;
    PORT
      LAYER met2 ;
        RECT 125.670 0.000 125.950 4.000 ;
    END
  END regs_tl_d_i[86]
  PIN regs_tl_d_i[87]
    DIRECTION INPUT ;
    USE SIGNAL ;
    PORT
      LAYER met2 ;
        RECT 128.890 0.000 129.170 4.000 ;
    END
  END regs_tl_d_i[87]
  PIN regs_tl_d_i[88]
    DIRECTION INPUT ;
    USE SIGNAL ;
    PORT
      LAYER met2 ;
        RECT 132.110 0.000 132.390 4.000 ;
    END
  END regs_tl_d_i[88]
  PIN regs_tl_d_i[89]
    DIRECTION INPUT ;
    USE SIGNAL ;
    PORT
      LAYER met2 ;
        RECT 135.330 0.000 135.610 4.000 ;
    END
  END regs_tl_d_i[89]
  PIN regs_tl_d_i[8]
    DIRECTION INPUT ;
    USE SIGNAL ;
    PORT
      LAYER met2 ;
        RECT 138.550 0.000 138.830 4.000 ;
    END
  END regs_tl_d_i[8]
  PIN regs_tl_d_i[90]
    DIRECTION INPUT ;
    USE SIGNAL ;
    PORT
      LAYER met2 ;
        RECT 141.770 0.000 142.050 4.000 ;
    END
  END regs_tl_d_i[90]
  PIN regs_tl_d_i[91]
    DIRECTION INPUT ;
    USE SIGNAL ;
    PORT
      LAYER met2 ;
        RECT 144.990 0.000 145.270 4.000 ;
    END
  END regs_tl_d_i[91]
  PIN regs_tl_d_i[92]
    DIRECTION INPUT ;
    USE SIGNAL ;
    PORT
      LAYER met2 ;
        RECT 148.210 0.000 148.490 4.000 ;
    END
  END regs_tl_d_i[92]
  PIN regs_tl_d_i[93]
    DIRECTION INPUT ;
    USE SIGNAL ;
    ANTENNAGATEAREA 0.631200 ;
    ANTENNADIFFAREA 0.434700 ;
    PORT
      LAYER met2 ;
        RECT 995.070 596.000 995.350 600.000 ;
    END
  END regs_tl_d_i[93]
  PIN regs_tl_d_i[94]
    DIRECTION INPUT ;
    USE SIGNAL ;
    ANTENNAGATEAREA 0.647700 ;
    ANTENNADIFFAREA 0.434700 ;
    PORT
      LAYER met2 ;
        RECT 721.370 596.000 721.650 600.000 ;
    END
  END regs_tl_d_i[94]
  PIN regs_tl_d_i[95]
    DIRECTION INPUT ;
    USE SIGNAL ;
    ANTENNAGATEAREA 0.631200 ;
    ANTENNADIFFAREA 0.434700 ;
    PORT
      LAYER met2 ;
        RECT 666.630 596.000 666.910 600.000 ;
    END
  END regs_tl_d_i[95]
  PIN regs_tl_d_i[96]
    DIRECTION INPUT ;
    USE SIGNAL ;
    ANTENNAGATEAREA 0.593700 ;
    ANTENNADIFFAREA 0.434700 ;
    PORT
      LAYER met2 ;
        RECT 1020.830 596.000 1021.110 600.000 ;
    END
  END regs_tl_d_i[96]
  PIN regs_tl_d_i[97]
    DIRECTION INPUT ;
    USE SIGNAL ;
    ANTENNAGATEAREA 0.631200 ;
    ANTENNADIFFAREA 0.434700 ;
    PORT
      LAYER met2 ;
        RECT 724.590 596.000 724.870 600.000 ;
    END
  END regs_tl_d_i[97]
  PIN regs_tl_d_i[98]
    DIRECTION INPUT ;
    USE SIGNAL ;
    ANTENNAGATEAREA 0.631200 ;
    ANTENNADIFFAREA 0.434700 ;
    PORT
      LAYER met2 ;
        RECT 705.270 596.000 705.550 600.000 ;
    END
  END regs_tl_d_i[98]
  PIN regs_tl_d_i[99]
    DIRECTION INPUT ;
    USE SIGNAL ;
    ANTENNAGATEAREA 0.631200 ;
    ANTENNADIFFAREA 0.434700 ;
    PORT
      LAYER met2 ;
        RECT 737.470 596.000 737.750 600.000 ;
    END
  END regs_tl_d_i[99]
  PIN regs_tl_d_i[9]
    DIRECTION INPUT ;
    USE SIGNAL ;
    PORT
      LAYER met2 ;
        RECT 151.430 0.000 151.710 4.000 ;
    END
  END regs_tl_d_i[9]
  PIN regs_tl_d_o[0]
    DIRECTION OUTPUT ;
    USE SIGNAL ;
    ANTENNADIFFAREA 0.445500 ;
    PORT
      LAYER met2 ;
        RECT 908.130 596.000 908.410 600.000 ;
    END
  END regs_tl_d_o[0]
  PIN regs_tl_d_o[10]
    DIRECTION OUTPUT ;
    USE SIGNAL ;
    ANTENNADIFFAREA 0.445500 ;
    PORT
      LAYER met2 ;
        RECT 1043.370 596.000 1043.650 600.000 ;
    END
  END regs_tl_d_o[10]
  PIN regs_tl_d_o[11]
    DIRECTION OUTPUT ;
    USE SIGNAL ;
    PORT
      LAYER met2 ;
        RECT 998.290 0.000 998.570 4.000 ;
    END
  END regs_tl_d_o[11]
  PIN regs_tl_d_o[12]
    DIRECTION OUTPUT ;
    USE SIGNAL ;
    ANTENNADIFFAREA 0.445500 ;
    PORT
      LAYER met2 ;
        RECT 692.390 596.000 692.670 600.000 ;
    END
  END regs_tl_d_o[12]
  PIN regs_tl_d_o[13]
    DIRECTION OUTPUT ;
    USE SIGNAL ;
    ANTENNADIFFAREA 0.445500 ;
    PORT
      LAYER met2 ;
        RECT 682.730 596.000 683.010 600.000 ;
    END
  END regs_tl_d_o[13]
  PIN regs_tl_d_o[14]
    DIRECTION OUTPUT ;
    USE SIGNAL ;
    ANTENNADIFFAREA 0.445500 ;
    PORT
      LAYER met2 ;
        RECT 718.150 596.000 718.430 600.000 ;
    END
  END regs_tl_d_o[14]
  PIN regs_tl_d_o[15]
    DIRECTION OUTPUT ;
    USE SIGNAL ;
    PORT
      LAYER met3 ;
        RECT 1296.000 295.840 1300.000 296.440 ;
    END
  END regs_tl_d_o[15]
  PIN regs_tl_d_o[16]
    DIRECTION OUTPUT ;
    USE SIGNAL ;
    ANTENNADIFFAREA 0.445500 ;
    PORT
      LAYER met2 ;
        RECT 943.550 596.000 943.830 600.000 ;
    END
  END regs_tl_d_o[16]
  PIN regs_tl_d_o[17]
    DIRECTION OUTPUT ;
    USE SIGNAL ;
    ANTENNADIFFAREA 0.445500 ;
    PORT
      LAYER met2 ;
        RECT 853.390 596.000 853.670 600.000 ;
    END
  END regs_tl_d_o[17]
  PIN regs_tl_d_o[18]
    DIRECTION OUTPUT ;
    USE SIGNAL ;
    ANTENNADIFFAREA 0.445500 ;
    PORT
      LAYER met2 ;
        RECT 872.710 596.000 872.990 600.000 ;
    END
  END regs_tl_d_o[18]
  PIN regs_tl_d_o[19]
    DIRECTION OUTPUT ;
    USE SIGNAL ;
    ANTENNADIFFAREA 0.445500 ;
    PORT
      LAYER met2 ;
        RECT 850.170 596.000 850.450 600.000 ;
    END
  END regs_tl_d_o[19]
  PIN regs_tl_d_o[1]
    DIRECTION OUTPUT ;
    USE SIGNAL ;
    PORT
      LAYER met2 ;
        RECT 209.390 0.000 209.670 4.000 ;
    END
  END regs_tl_d_o[1]
  PIN regs_tl_d_o[20]
    DIRECTION OUTPUT ;
    USE SIGNAL ;
    ANTENNADIFFAREA 0.445500 ;
    PORT
      LAYER met2 ;
        RECT 856.610 596.000 856.890 600.000 ;
    END
  END regs_tl_d_o[20]
  PIN regs_tl_d_o[21]
    DIRECTION OUTPUT ;
    USE SIGNAL ;
    ANTENNADIFFAREA 0.445500 ;
    PORT
      LAYER met2 ;
        RECT 866.270 596.000 866.550 600.000 ;
    END
  END regs_tl_d_o[21]
  PIN regs_tl_d_o[22]
    DIRECTION OUTPUT ;
    USE SIGNAL ;
    ANTENNADIFFAREA 0.445500 ;
    PORT
      LAYER met2 ;
        RECT 949.990 596.000 950.270 600.000 ;
    END
  END regs_tl_d_o[22]
  PIN regs_tl_d_o[23]
    DIRECTION OUTPUT ;
    USE SIGNAL ;
    ANTENNADIFFAREA 0.445500 ;
    PORT
      LAYER met2 ;
        RECT 846.950 596.000 847.230 600.000 ;
    END
  END regs_tl_d_o[23]
  PIN regs_tl_d_o[24]
    DIRECTION OUTPUT ;
    USE SIGNAL ;
    ANTENNADIFFAREA 0.445500 ;
    PORT
      LAYER met2 ;
        RECT 895.250 596.000 895.530 600.000 ;
    END
  END regs_tl_d_o[24]
  PIN regs_tl_d_o[25]
    DIRECTION OUTPUT ;
    USE SIGNAL ;
    ANTENNADIFFAREA 0.445500 ;
    PORT
      LAYER met2 ;
        RECT 937.110 596.000 937.390 600.000 ;
    END
  END regs_tl_d_o[25]
  PIN regs_tl_d_o[26]
    DIRECTION OUTPUT ;
    USE SIGNAL ;
    ANTENNADIFFAREA 0.445500 ;
    PORT
      LAYER met2 ;
        RECT 882.370 596.000 882.650 600.000 ;
    END
  END regs_tl_d_o[26]
  PIN regs_tl_d_o[27]
    DIRECTION OUTPUT ;
    USE SIGNAL ;
    ANTENNADIFFAREA 0.445500 ;
    PORT
      LAYER met2 ;
        RECT 879.150 596.000 879.430 600.000 ;
    END
  END regs_tl_d_o[27]
  PIN regs_tl_d_o[28]
    DIRECTION OUTPUT ;
    USE SIGNAL ;
    ANTENNADIFFAREA 0.445500 ;
    PORT
      LAYER met2 ;
        RECT 898.470 596.000 898.750 600.000 ;
    END
  END regs_tl_d_o[28]
  PIN regs_tl_d_o[29]
    DIRECTION OUTPUT ;
    USE SIGNAL ;
    ANTENNADIFFAREA 0.445500 ;
    PORT
      LAYER met2 ;
        RECT 892.030 596.000 892.310 600.000 ;
    END
  END regs_tl_d_o[29]
  PIN regs_tl_d_o[2]
    DIRECTION OUTPUT ;
    USE SIGNAL ;
    ANTENNADIFFAREA 0.445500 ;
    PORT
      LAYER met2 ;
        RECT 875.930 596.000 876.210 600.000 ;
    END
  END regs_tl_d_o[2]
  PIN regs_tl_d_o[30]
    DIRECTION OUTPUT ;
    USE SIGNAL ;
    ANTENNADIFFAREA 0.445500 ;
    PORT
      LAYER met2 ;
        RECT 885.590 596.000 885.870 600.000 ;
    END
  END regs_tl_d_o[30]
  PIN regs_tl_d_o[31]
    DIRECTION OUTPUT ;
    USE SIGNAL ;
    ANTENNADIFFAREA 0.445500 ;
    PORT
      LAYER met2 ;
        RECT 840.510 596.000 840.790 600.000 ;
    END
  END regs_tl_d_o[31]
  PIN regs_tl_d_o[32]
    DIRECTION OUTPUT ;
    USE SIGNAL ;
    ANTENNADIFFAREA 0.445500 ;
    PORT
      LAYER met2 ;
        RECT 824.410 596.000 824.690 600.000 ;
    END
  END regs_tl_d_o[32]
  PIN regs_tl_d_o[33]
    DIRECTION OUTPUT ;
    USE SIGNAL ;
    ANTENNADIFFAREA 0.445500 ;
    PORT
      LAYER met2 ;
        RECT 811.530 596.000 811.810 600.000 ;
    END
  END regs_tl_d_o[33]
  PIN regs_tl_d_o[34]
    DIRECTION OUTPUT ;
    USE SIGNAL ;
    ANTENNADIFFAREA 0.445500 ;
    PORT
      LAYER met2 ;
        RECT 837.290 596.000 837.570 600.000 ;
    END
  END regs_tl_d_o[34]
  PIN regs_tl_d_o[35]
    DIRECTION OUTPUT ;
    USE SIGNAL ;
    ANTENNADIFFAREA 0.445500 ;
    PORT
      LAYER met2 ;
        RECT 805.090 596.000 805.370 600.000 ;
    END
  END regs_tl_d_o[35]
  PIN regs_tl_d_o[36]
    DIRECTION OUTPUT ;
    USE SIGNAL ;
    ANTENNADIFFAREA 0.445500 ;
    PORT
      LAYER met2 ;
        RECT 808.310 596.000 808.590 600.000 ;
    END
  END regs_tl_d_o[36]
  PIN regs_tl_d_o[37]
    DIRECTION OUTPUT ;
    USE SIGNAL ;
    ANTENNADIFFAREA 0.445500 ;
    PORT
      LAYER met2 ;
        RECT 821.190 596.000 821.470 600.000 ;
    END
  END regs_tl_d_o[37]
  PIN regs_tl_d_o[38]
    DIRECTION OUTPUT ;
    USE SIGNAL ;
    ANTENNADIFFAREA 0.445500 ;
    PORT
      LAYER met2 ;
        RECT 814.750 596.000 815.030 600.000 ;
    END
  END regs_tl_d_o[38]
  PIN regs_tl_d_o[39]
    DIRECTION OUTPUT ;
    USE SIGNAL ;
    ANTENNADIFFAREA 0.445500 ;
    PORT
      LAYER met2 ;
        RECT 956.430 596.000 956.710 600.000 ;
    END
  END regs_tl_d_o[39]
  PIN regs_tl_d_o[3]
    DIRECTION OUTPUT ;
    USE SIGNAL ;
    ANTENNADIFFAREA 0.445500 ;
    PORT
      LAYER met2 ;
        RECT 795.430 596.000 795.710 600.000 ;
    END
  END regs_tl_d_o[3]
  PIN regs_tl_d_o[40]
    DIRECTION OUTPUT ;
    USE SIGNAL ;
    ANTENNADIFFAREA 0.445500 ;
    PORT
      LAYER met2 ;
        RECT 969.310 596.000 969.590 600.000 ;
    END
  END regs_tl_d_o[40]
  PIN regs_tl_d_o[41]
    DIRECTION OUTPUT ;
    USE SIGNAL ;
    ANTENNADIFFAREA 0.445500 ;
    PORT
      LAYER met2 ;
        RECT 801.870 596.000 802.150 600.000 ;
    END
  END regs_tl_d_o[41]
  PIN regs_tl_d_o[42]
    DIRECTION OUTPUT ;
    USE SIGNAL ;
    ANTENNADIFFAREA 0.445500 ;
    PORT
      LAYER met2 ;
        RECT 798.650 596.000 798.930 600.000 ;
    END
  END regs_tl_d_o[42]
  PIN regs_tl_d_o[43]
    DIRECTION OUTPUT ;
    USE SIGNAL ;
    ANTENNADIFFAREA 0.445500 ;
    PORT
      LAYER met2 ;
        RECT 946.770 596.000 947.050 600.000 ;
    END
  END regs_tl_d_o[43]
  PIN regs_tl_d_o[44]
    DIRECTION OUTPUT ;
    USE SIGNAL ;
    ANTENNADIFFAREA 0.445500 ;
    PORT
      LAYER met2 ;
        RECT 788.990 596.000 789.270 600.000 ;
    END
  END regs_tl_d_o[44]
  PIN regs_tl_d_o[45]
    DIRECTION OUTPUT ;
    USE SIGNAL ;
    ANTENNADIFFAREA 0.445500 ;
    PORT
      LAYER met2 ;
        RECT 843.730 596.000 844.010 600.000 ;
    END
  END regs_tl_d_o[45]
  PIN regs_tl_d_o[46]
    DIRECTION OUTPUT ;
    USE SIGNAL ;
    ANTENNADIFFAREA 0.445500 ;
    PORT
      LAYER met2 ;
        RECT 972.530 596.000 972.810 600.000 ;
    END
  END regs_tl_d_o[46]
  PIN regs_tl_d_o[47]
    DIRECTION OUTPUT ;
    USE SIGNAL ;
    ANTENNADIFFAREA 0.445500 ;
    PORT
      LAYER met2 ;
        RECT 785.770 596.000 786.050 600.000 ;
    END
  END regs_tl_d_o[47]
  PIN regs_tl_d_o[48]
    DIRECTION OUTPUT ;
    USE SIGNAL ;
    PORT
      LAYER met2 ;
        RECT 898.470 0.000 898.750 4.000 ;
    END
  END regs_tl_d_o[48]
  PIN regs_tl_d_o[49]
    DIRECTION OUTPUT ;
    USE SIGNAL ;
    ANTENNADIFFAREA 0.445500 ;
    PORT
      LAYER met2 ;
        RECT 991.850 596.000 992.130 600.000 ;
    END
  END regs_tl_d_o[49]
  PIN regs_tl_d_o[4]
    DIRECTION OUTPUT ;
    USE SIGNAL ;
    ANTENNADIFFAREA 0.445500 ;
    PORT
      LAYER met2 ;
        RECT 834.070 596.000 834.350 600.000 ;
    END
  END regs_tl_d_o[4]
  PIN regs_tl_d_o[50]
    DIRECTION OUTPUT ;
    USE SIGNAL ;
    ANTENNADIFFAREA 0.445500 ;
    PORT
      LAYER met2 ;
        RECT 1004.730 596.000 1005.010 600.000 ;
    END
  END regs_tl_d_o[50]
  PIN regs_tl_d_o[51]
    DIRECTION OUTPUT ;
    USE SIGNAL ;
    ANTENNADIFFAREA 0.445500 ;
    PORT
      LAYER met2 ;
        RECT 673.070 596.000 673.350 600.000 ;
    END
  END regs_tl_d_o[51]
  PIN regs_tl_d_o[52]
    DIRECTION OUTPUT ;
    USE SIGNAL ;
    ANTENNADIFFAREA 0.445500 ;
    PORT
      LAYER met2 ;
        RECT 714.930 596.000 715.210 600.000 ;
    END
  END regs_tl_d_o[52]
  PIN regs_tl_d_o[53]
    DIRECTION OUTPUT ;
    USE SIGNAL ;
    ANTENNADIFFAREA 0.445500 ;
    PORT
      LAYER met2 ;
        RECT 727.810 596.000 728.090 600.000 ;
    END
  END regs_tl_d_o[53]
  PIN regs_tl_d_o[54]
    DIRECTION OUTPUT ;
    USE SIGNAL ;
    ANTENNADIFFAREA 0.445500 ;
    PORT
      LAYER met2 ;
        RECT 708.490 596.000 708.770 600.000 ;
    END
  END regs_tl_d_o[54]
  PIN regs_tl_d_o[55]
    DIRECTION OUTPUT ;
    USE SIGNAL ;
    ANTENNADIFFAREA 0.445500 ;
    PORT
      LAYER met2 ;
        RECT 740.690 596.000 740.970 600.000 ;
    END
  END regs_tl_d_o[55]
  PIN regs_tl_d_o[56]
    DIRECTION OUTPUT ;
    USE SIGNAL ;
    ANTENNADIFFAREA 0.445500 ;
    PORT
      LAYER met2 ;
        RECT 750.350 596.000 750.630 600.000 ;
    END
  END regs_tl_d_o[56]
  PIN regs_tl_d_o[57]
    DIRECTION OUTPUT ;
    USE SIGNAL ;
    ANTENNADIFFAREA 0.445500 ;
    PORT
      LAYER met2 ;
        RECT 695.610 596.000 695.890 600.000 ;
    END
  END regs_tl_d_o[57]
  PIN regs_tl_d_o[58]
    DIRECTION OUTPUT ;
    USE SIGNAL ;
    ANTENNADIFFAREA 0.445500 ;
    PORT
      LAYER met2 ;
        RECT 679.510 596.000 679.790 600.000 ;
    END
  END regs_tl_d_o[58]
  PIN regs_tl_d_o[59]
    DIRECTION OUTPUT ;
    USE SIGNAL ;
    PORT
      LAYER met2 ;
        RECT 1007.950 0.000 1008.230 4.000 ;
    END
  END regs_tl_d_o[59]
  PIN regs_tl_d_o[5]
    DIRECTION OUTPUT ;
    USE SIGNAL ;
    ANTENNADIFFAREA 0.445500 ;
    PORT
      LAYER met2 ;
        RECT 859.830 596.000 860.110 600.000 ;
    END
  END regs_tl_d_o[5]
  PIN regs_tl_d_o[60]
    DIRECTION OUTPUT ;
    USE SIGNAL ;
    PORT
      LAYER met2 ;
        RECT 933.890 0.000 934.170 4.000 ;
    END
  END regs_tl_d_o[60]
  PIN regs_tl_d_o[61]
    DIRECTION OUTPUT ;
    USE SIGNAL ;
    PORT
      LAYER met2 ;
        RECT 888.810 596.000 889.090 600.000 ;
    END
  END regs_tl_d_o[61]
  PIN regs_tl_d_o[62]
    DIRECTION OUTPUT ;
    USE SIGNAL ;
    ANTENNADIFFAREA 0.445500 ;
    PORT
      LAYER met2 ;
        RECT 982.190 596.000 982.470 600.000 ;
    END
  END regs_tl_d_o[62]
  PIN regs_tl_d_o[63]
    DIRECTION OUTPUT ;
    USE SIGNAL ;
    PORT
      LAYER met2 ;
        RECT 782.550 596.000 782.830 600.000 ;
    END
  END regs_tl_d_o[63]
  PIN regs_tl_d_o[64]
    DIRECTION OUTPUT ;
    USE SIGNAL ;
    PORT
      LAYER met2 ;
        RECT 776.110 596.000 776.390 600.000 ;
    END
  END regs_tl_d_o[64]
  PIN regs_tl_d_o[65]
    DIRECTION OUTPUT ;
    USE SIGNAL ;
    ANTENNADIFFAREA 0.445500 ;
    PORT
      LAYER met2 ;
        RECT 904.910 596.000 905.190 600.000 ;
    END
  END regs_tl_d_o[65]
  PIN regs_tl_d_o[6]
    DIRECTION OUTPUT ;
    USE SIGNAL ;
    ANTENNADIFFAREA 0.445500 ;
    PORT
      LAYER met2 ;
        RECT 869.490 596.000 869.770 600.000 ;
    END
  END regs_tl_d_o[6]
  PIN regs_tl_d_o[7]
    DIRECTION OUTPUT ;
    USE SIGNAL ;
    ANTENNADIFFAREA 0.445500 ;
    PORT
      LAYER met2 ;
        RECT 830.850 596.000 831.130 600.000 ;
    END
  END regs_tl_d_o[7]
  PIN regs_tl_d_o[8]
    DIRECTION OUTPUT ;
    USE SIGNAL ;
    ANTENNADIFFAREA 0.445500 ;
    PORT
      LAYER met2 ;
        RECT 863.050 596.000 863.330 600.000 ;
    END
  END regs_tl_d_o[8]
  PIN regs_tl_d_o[9]
    DIRECTION OUTPUT ;
    USE SIGNAL ;
    ANTENNADIFFAREA 0.445500 ;
    PORT
      LAYER met2 ;
        RECT 1040.150 596.000 1040.430 600.000 ;
    END
  END regs_tl_d_o[9]
  PIN rst_ni
    DIRECTION INPUT ;
    USE SIGNAL ;
    ANTENNAGATEAREA 0.593700 ;
    ANTENNADIFFAREA 0.434700 ;
    PORT
      LAYER met2 ;
        RECT 921.010 0.000 921.290 4.000 ;
    END
  END rst_ni
  PIN sba_tl_h_i[0]
    DIRECTION INPUT ;
    USE SIGNAL ;
    ANTENNAGATEAREA 0.631200 ;
    ANTENNADIFFAREA 0.434700 ;
    PORT
      LAYER met2 ;
        RECT 589.350 0.000 589.630 4.000 ;
    END
  END sba_tl_h_i[0]
  PIN sba_tl_h_i[10]
    DIRECTION INPUT ;
    USE SIGNAL ;
    PORT
      LAYER met2 ;
        RECT 154.650 0.000 154.930 4.000 ;
    END
  END sba_tl_h_i[10]
  PIN sba_tl_h_i[11]
    DIRECTION INPUT ;
    USE SIGNAL ;
    PORT
      LAYER met2 ;
        RECT 157.870 0.000 158.150 4.000 ;
    END
  END sba_tl_h_i[11]
  PIN sba_tl_h_i[12]
    DIRECTION INPUT ;
    USE SIGNAL ;
    PORT
      LAYER met2 ;
        RECT 161.090 0.000 161.370 4.000 ;
    END
  END sba_tl_h_i[12]
  PIN sba_tl_h_i[13]
    DIRECTION INPUT ;
    USE SIGNAL ;
    PORT
      LAYER met2 ;
        RECT 164.310 0.000 164.590 4.000 ;
    END
  END sba_tl_h_i[13]
  PIN sba_tl_h_i[14]
    DIRECTION INPUT ;
    USE SIGNAL ;
    PORT
      LAYER met2 ;
        RECT 167.530 0.000 167.810 4.000 ;
    END
  END sba_tl_h_i[14]
  PIN sba_tl_h_i[15]
    DIRECTION INPUT ;
    USE SIGNAL ;
    PORT
      LAYER met2 ;
        RECT 170.750 0.000 171.030 4.000 ;
    END
  END sba_tl_h_i[15]
  PIN sba_tl_h_i[16]
    DIRECTION INPUT ;
    USE SIGNAL ;
    ANTENNAGATEAREA 0.631200 ;
    ANTENNADIFFAREA 0.434700 ;
    PORT
      LAYER met2 ;
        RECT 756.790 0.000 757.070 4.000 ;
    END
  END sba_tl_h_i[16]
  PIN sba_tl_h_i[17]
    DIRECTION INPUT ;
    USE SIGNAL ;
    ANTENNAGATEAREA 0.631200 ;
    ANTENNADIFFAREA 0.434700 ;
    PORT
      LAYER met2 ;
        RECT 827.630 0.000 827.910 4.000 ;
    END
  END sba_tl_h_i[17]
  PIN sba_tl_h_i[18]
    DIRECTION INPUT ;
    USE SIGNAL ;
    ANTENNAGATEAREA 0.631200 ;
    ANTENNADIFFAREA 0.434700 ;
    PORT
      LAYER met2 ;
        RECT 843.730 0.000 844.010 4.000 ;
    END
  END sba_tl_h_i[18]
  PIN sba_tl_h_i[19]
    DIRECTION INPUT ;
    USE SIGNAL ;
    ANTENNAGATEAREA 0.631200 ;
    ANTENNADIFFAREA 0.434700 ;
    PORT
      LAYER met2 ;
        RECT 634.430 0.000 634.710 4.000 ;
    END
  END sba_tl_h_i[19]
  PIN sba_tl_h_i[1]
    DIRECTION INPUT ;
    USE SIGNAL ;
    ANTENNAGATEAREA 0.560700 ;
    ANTENNADIFFAREA 0.434700 ;
    PORT
      LAYER met2 ;
        RECT 595.790 0.000 596.070 4.000 ;
    END
  END sba_tl_h_i[1]
  PIN sba_tl_h_i[20]
    DIRECTION INPUT ;
    USE SIGNAL ;
    ANTENNAGATEAREA 0.647700 ;
    ANTENNADIFFAREA 0.434700 ;
    PORT
      LAYER met2 ;
        RECT 911.350 0.000 911.630 4.000 ;
    END
  END sba_tl_h_i[20]
  PIN sba_tl_h_i[21]
    DIRECTION INPUT ;
    USE SIGNAL ;
    ANTENNAGATEAREA 0.631200 ;
    ANTENNADIFFAREA 0.434700 ;
    PORT
      LAYER met2 ;
        RECT 673.070 0.000 673.350 4.000 ;
    END
  END sba_tl_h_i[21]
  PIN sba_tl_h_i[22]
    DIRECTION INPUT ;
    USE SIGNAL ;
    ANTENNAGATEAREA 0.631200 ;
    ANTENNADIFFAREA 0.434700 ;
    PORT
      LAYER met2 ;
        RECT 676.290 0.000 676.570 4.000 ;
    END
  END sba_tl_h_i[22]
  PIN sba_tl_h_i[23]
    DIRECTION INPUT ;
    USE SIGNAL ;
    ANTENNAGATEAREA 0.631200 ;
    ANTENNADIFFAREA 0.434700 ;
    PORT
      LAYER met2 ;
        RECT 615.110 0.000 615.390 4.000 ;
    END
  END sba_tl_h_i[23]
  PIN sba_tl_h_i[24]
    DIRECTION INPUT ;
    USE SIGNAL ;
    ANTENNAGATEAREA 0.631200 ;
    ANTENNADIFFAREA 0.434700 ;
    PORT
      LAYER met2 ;
        RECT 760.010 0.000 760.290 4.000 ;
    END
  END sba_tl_h_i[24]
  PIN sba_tl_h_i[25]
    DIRECTION INPUT ;
    USE SIGNAL ;
    ANTENNAGATEAREA 0.631200 ;
    ANTENNADIFFAREA 0.434700 ;
    PORT
      LAYER met2 ;
        RECT 718.150 0.000 718.430 4.000 ;
    END
  END sba_tl_h_i[25]
  PIN sba_tl_h_i[26]
    DIRECTION INPUT ;
    USE SIGNAL ;
    ANTENNAGATEAREA 0.631200 ;
    ANTENNADIFFAREA 0.434700 ;
    PORT
      LAYER met2 ;
        RECT 888.810 0.000 889.090 4.000 ;
    END
  END sba_tl_h_i[26]
  PIN sba_tl_h_i[27]
    DIRECTION INPUT ;
    USE SIGNAL ;
    ANTENNAGATEAREA 0.631200 ;
    ANTENNADIFFAREA 0.434700 ;
    PORT
      LAYER met2 ;
        RECT 640.870 0.000 641.150 4.000 ;
    END
  END sba_tl_h_i[27]
  PIN sba_tl_h_i[28]
    DIRECTION INPUT ;
    USE SIGNAL ;
    ANTENNAGATEAREA 0.631200 ;
    ANTENNADIFFAREA 0.434700 ;
    PORT
      LAYER met2 ;
        RECT 679.510 0.000 679.790 4.000 ;
    END
  END sba_tl_h_i[28]
  PIN sba_tl_h_i[29]
    DIRECTION INPUT ;
    USE SIGNAL ;
    ANTENNAGATEAREA 0.647700 ;
    ANTENNADIFFAREA 0.434700 ;
    PORT
      LAYER met2 ;
        RECT 882.370 0.000 882.650 4.000 ;
    END
  END sba_tl_h_i[29]
  PIN sba_tl_h_i[2]
    DIRECTION INPUT ;
    USE SIGNAL ;
    PORT
      LAYER met2 ;
        RECT 173.970 0.000 174.250 4.000 ;
    END
  END sba_tl_h_i[2]
  PIN sba_tl_h_i[30]
    DIRECTION INPUT ;
    USE SIGNAL ;
    ANTENNAGATEAREA 0.631200 ;
    ANTENNADIFFAREA 0.434700 ;
    PORT
      LAYER met2 ;
        RECT 656.970 0.000 657.250 4.000 ;
    END
  END sba_tl_h_i[30]
  PIN sba_tl_h_i[31]
    DIRECTION INPUT ;
    USE SIGNAL ;
    ANTENNAGATEAREA 0.631200 ;
    ANTENNADIFFAREA 0.434700 ;
    PORT
      LAYER met2 ;
        RECT 605.450 0.000 605.730 4.000 ;
    END
  END sba_tl_h_i[31]
  PIN sba_tl_h_i[32]
    DIRECTION INPUT ;
    USE SIGNAL ;
    ANTENNAGATEAREA 0.631200 ;
    ANTENNADIFFAREA 0.434700 ;
    PORT
      LAYER met2 ;
        RECT 872.710 0.000 872.990 4.000 ;
    END
  END sba_tl_h_i[32]
  PIN sba_tl_h_i[33]
    DIRECTION INPUT ;
    USE SIGNAL ;
    ANTENNAGATEAREA 0.631200 ;
    ANTENNADIFFAREA 0.434700 ;
    PORT
      LAYER met2 ;
        RECT 734.250 0.000 734.530 4.000 ;
    END
  END sba_tl_h_i[33]
  PIN sba_tl_h_i[34]
    DIRECTION INPUT ;
    USE SIGNAL ;
    ANTENNAGATEAREA 0.631200 ;
    ANTENNADIFFAREA 0.434700 ;
    PORT
      LAYER met2 ;
        RECT 895.250 0.000 895.530 4.000 ;
    END
  END sba_tl_h_i[34]
  PIN sba_tl_h_i[35]
    DIRECTION INPUT ;
    USE SIGNAL ;
    ANTENNAGATEAREA 0.631200 ;
    ANTENNADIFFAREA 0.434700 ;
    PORT
      LAYER met2 ;
        RECT 647.310 0.000 647.590 4.000 ;
    END
  END sba_tl_h_i[35]
  PIN sba_tl_h_i[36]
    DIRECTION INPUT ;
    USE SIGNAL ;
    ANTENNAGATEAREA 0.631200 ;
    ANTENNADIFFAREA 0.434700 ;
    PORT
      LAYER met2 ;
        RECT 724.590 0.000 724.870 4.000 ;
    END
  END sba_tl_h_i[36]
  PIN sba_tl_h_i[37]
    DIRECTION INPUT ;
    USE SIGNAL ;
    ANTENNAGATEAREA 0.631200 ;
    ANTENNADIFFAREA 0.434700 ;
    PORT
      LAYER met2 ;
        RECT 711.710 0.000 711.990 4.000 ;
    END
  END sba_tl_h_i[37]
  PIN sba_tl_h_i[38]
    DIRECTION INPUT ;
    USE SIGNAL ;
    ANTENNAGATEAREA 0.631200 ;
    ANTENNADIFFAREA 0.434700 ;
    PORT
      LAYER met2 ;
        RECT 663.410 0.000 663.690 4.000 ;
    END
  END sba_tl_h_i[38]
  PIN sba_tl_h_i[39]
    DIRECTION INPUT ;
    USE SIGNAL ;
    ANTENNAGATEAREA 0.631200 ;
    ANTENNADIFFAREA 0.434700 ;
    PORT
      LAYER met2 ;
        RECT 611.890 0.000 612.170 4.000 ;
    END
  END sba_tl_h_i[39]
  PIN sba_tl_h_i[3]
    DIRECTION INPUT ;
    USE SIGNAL ;
    PORT
      LAYER met2 ;
        RECT 177.190 0.000 177.470 4.000 ;
    END
  END sba_tl_h_i[3]
  PIN sba_tl_h_i[40]
    DIRECTION INPUT ;
    USE SIGNAL ;
    ANTENNAGATEAREA 0.631200 ;
    ANTENNADIFFAREA 0.434700 ;
    PORT
      LAYER met2 ;
        RECT 792.210 0.000 792.490 4.000 ;
    END
  END sba_tl_h_i[40]
  PIN sba_tl_h_i[41]
    DIRECTION INPUT ;
    USE SIGNAL ;
    ANTENNAGATEAREA 0.560700 ;
    ANTENNADIFFAREA 0.434700 ;
    PORT
      LAYER met2 ;
        RECT 834.070 0.000 834.350 4.000 ;
    END
  END sba_tl_h_i[41]
  PIN sba_tl_h_i[42]
    DIRECTION INPUT ;
    USE SIGNAL ;
    ANTENNAGATEAREA 0.631200 ;
    ANTENNADIFFAREA 0.434700 ;
    PORT
      LAYER met2 ;
        RECT 846.950 0.000 847.230 4.000 ;
    END
  END sba_tl_h_i[42]
  PIN sba_tl_h_i[43]
    DIRECTION INPUT ;
    USE SIGNAL ;
    ANTENNAGATEAREA 0.631200 ;
    ANTENNADIFFAREA 0.434700 ;
    PORT
      LAYER met2 ;
        RECT 682.730 0.000 683.010 4.000 ;
    END
  END sba_tl_h_i[43]
  PIN sba_tl_h_i[44]
    DIRECTION INPUT ;
    USE SIGNAL ;
    ANTENNAGATEAREA 0.631200 ;
    ANTENNADIFFAREA 0.434700 ;
    PORT
      LAYER met2 ;
        RECT 737.470 0.000 737.750 4.000 ;
    END
  END sba_tl_h_i[44]
  PIN sba_tl_h_i[45]
    DIRECTION INPUT ;
    USE SIGNAL ;
    ANTENNAGATEAREA 0.631200 ;
    ANTENNADIFFAREA 0.434700 ;
    PORT
      LAYER met2 ;
        RECT 692.390 0.000 692.670 4.000 ;
    END
  END sba_tl_h_i[45]
  PIN sba_tl_h_i[46]
    DIRECTION INPUT ;
    USE SIGNAL ;
    ANTENNAGATEAREA 0.647700 ;
    ANTENNADIFFAREA 0.434700 ;
    PORT
      LAYER met2 ;
        RECT 660.190 0.000 660.470 4.000 ;
    END
  END sba_tl_h_i[46]
  PIN sba_tl_h_i[47]
    DIRECTION INPUT ;
    USE SIGNAL ;
    ANTENNAGATEAREA 0.647700 ;
    ANTENNADIFFAREA 0.434700 ;
    PORT
      LAYER met2 ;
        RECT 618.330 0.000 618.610 4.000 ;
    END
  END sba_tl_h_i[47]
  PIN sba_tl_h_i[48]
    DIRECTION INPUT ;
    USE SIGNAL ;
    PORT
      LAYER met2 ;
        RECT 180.410 0.000 180.690 4.000 ;
    END
  END sba_tl_h_i[48]
  PIN sba_tl_h_i[49]
    DIRECTION INPUT ;
    USE SIGNAL ;
    PORT
      LAYER met2 ;
        RECT 183.630 0.000 183.910 4.000 ;
    END
  END sba_tl_h_i[49]
  PIN sba_tl_h_i[4]
    DIRECTION INPUT ;
    USE SIGNAL ;
    PORT
      LAYER met2 ;
        RECT 186.850 0.000 187.130 4.000 ;
    END
  END sba_tl_h_i[4]
  PIN sba_tl_h_i[50]
    DIRECTION INPUT ;
    USE SIGNAL ;
    PORT
      LAYER met2 ;
        RECT 190.070 0.000 190.350 4.000 ;
    END
  END sba_tl_h_i[50]
  PIN sba_tl_h_i[51]
    DIRECTION INPUT ;
    USE SIGNAL ;
    PORT
      LAYER met2 ;
        RECT 193.290 0.000 193.570 4.000 ;
    END
  END sba_tl_h_i[51]
  PIN sba_tl_h_i[52]
    DIRECTION INPUT ;
    USE SIGNAL ;
    PORT
      LAYER met2 ;
        RECT 196.510 0.000 196.790 4.000 ;
    END
  END sba_tl_h_i[52]
  PIN sba_tl_h_i[53]
    DIRECTION INPUT ;
    USE SIGNAL ;
    PORT
      LAYER met2 ;
        RECT 199.730 0.000 200.010 4.000 ;
    END
  END sba_tl_h_i[53]
  PIN sba_tl_h_i[54]
    DIRECTION INPUT ;
    USE SIGNAL ;
    PORT
      LAYER met2 ;
        RECT 202.950 0.000 203.230 4.000 ;
    END
  END sba_tl_h_i[54]
  PIN sba_tl_h_i[55]
    DIRECTION INPUT ;
    USE SIGNAL ;
    PORT
      LAYER met2 ;
        RECT 206.170 0.000 206.450 4.000 ;
    END
  END sba_tl_h_i[55]
  PIN sba_tl_h_i[56]
    DIRECTION INPUT ;
    USE SIGNAL ;
    PORT
      LAYER met2 ;
        RECT 212.610 0.000 212.890 4.000 ;
    END
  END sba_tl_h_i[56]
  PIN sba_tl_h_i[57]
    DIRECTION INPUT ;
    USE SIGNAL ;
    PORT
      LAYER met2 ;
        RECT 215.830 0.000 216.110 4.000 ;
    END
  END sba_tl_h_i[57]
  PIN sba_tl_h_i[58]
    DIRECTION INPUT ;
    USE SIGNAL ;
    PORT
      LAYER met2 ;
        RECT 219.050 0.000 219.330 4.000 ;
    END
  END sba_tl_h_i[58]
  PIN sba_tl_h_i[59]
    DIRECTION INPUT ;
    USE SIGNAL ;
    PORT
      LAYER met2 ;
        RECT 222.270 0.000 222.550 4.000 ;
    END
  END sba_tl_h_i[59]
  PIN sba_tl_h_i[5]
    DIRECTION INPUT ;
    USE SIGNAL ;
    PORT
      LAYER met2 ;
        RECT 225.490 0.000 225.770 4.000 ;
    END
  END sba_tl_h_i[5]
  PIN sba_tl_h_i[60]
    DIRECTION INPUT ;
    USE SIGNAL ;
    PORT
      LAYER met2 ;
        RECT 228.710 0.000 228.990 4.000 ;
    END
  END sba_tl_h_i[60]
  PIN sba_tl_h_i[61]
    DIRECTION INPUT ;
    USE SIGNAL ;
    PORT
      LAYER met2 ;
        RECT 231.930 0.000 232.210 4.000 ;
    END
  END sba_tl_h_i[61]
  PIN sba_tl_h_i[62]
    DIRECTION INPUT ;
    USE SIGNAL ;
    PORT
      LAYER met2 ;
        RECT 235.150 0.000 235.430 4.000 ;
    END
  END sba_tl_h_i[62]
  PIN sba_tl_h_i[63]
    DIRECTION INPUT ;
    USE SIGNAL ;
    PORT
      LAYER met2 ;
        RECT 238.370 0.000 238.650 4.000 ;
    END
  END sba_tl_h_i[63]
  PIN sba_tl_h_i[64]
    DIRECTION INPUT ;
    USE SIGNAL ;
    PORT
      LAYER met2 ;
        RECT 241.590 0.000 241.870 4.000 ;
    END
  END sba_tl_h_i[64]
  PIN sba_tl_h_i[65]
    DIRECTION INPUT ;
    USE SIGNAL ;
    ANTENNAGATEAREA 0.631200 ;
    ANTENNADIFFAREA 0.434700 ;
    PORT
      LAYER met2 ;
        RECT 576.470 0.000 576.750 4.000 ;
    END
  END sba_tl_h_i[65]
  PIN sba_tl_h_i[6]
    DIRECTION INPUT ;
    USE SIGNAL ;
    PORT
      LAYER met2 ;
        RECT 244.810 0.000 245.090 4.000 ;
    END
  END sba_tl_h_i[6]
  PIN sba_tl_h_i[7]
    DIRECTION INPUT ;
    USE SIGNAL ;
    PORT
      LAYER met2 ;
        RECT 248.030 0.000 248.310 4.000 ;
    END
  END sba_tl_h_i[7]
  PIN sba_tl_h_i[8]
    DIRECTION INPUT ;
    USE SIGNAL ;
    PORT
      LAYER met2 ;
        RECT 251.250 0.000 251.530 4.000 ;
    END
  END sba_tl_h_i[8]
  PIN sba_tl_h_i[9]
    DIRECTION INPUT ;
    USE SIGNAL ;
    PORT
      LAYER met2 ;
        RECT 254.470 0.000 254.750 4.000 ;
    END
  END sba_tl_h_i[9]
  PIN sba_tl_h_o[0]
    DIRECTION OUTPUT ;
    USE SIGNAL ;
    PORT
      LAYER met3 ;
        RECT 1296.000 289.040 1300.000 289.640 ;
    END
  END sba_tl_h_o[0]
  PIN sba_tl_h_o[100]
    DIRECTION OUTPUT ;
    USE SIGNAL ;
    PORT
      LAYER met2 ;
        RECT 566.810 596.000 567.090 600.000 ;
    END
  END sba_tl_h_o[100]
  PIN sba_tl_h_o[101]
    DIRECTION OUTPUT ;
    USE SIGNAL ;
    PORT
      LAYER met2 ;
        RECT 817.970 596.000 818.250 600.000 ;
    END
  END sba_tl_h_o[101]
  PIN sba_tl_h_o[102]
    DIRECTION OUTPUT ;
    USE SIGNAL ;
    PORT
      LAYER met3 ;
        RECT 1296.000 391.040 1300.000 391.640 ;
    END
  END sba_tl_h_o[102]
  PIN sba_tl_h_o[103]
    DIRECTION OUTPUT ;
    USE SIGNAL ;
    PORT
      LAYER met2 ;
        RECT 586.130 0.000 586.410 4.000 ;
    END
  END sba_tl_h_o[103]
  PIN sba_tl_h_o[104]
    DIRECTION OUTPUT ;
    USE SIGNAL ;
    PORT
      LAYER met2 ;
        RECT 930.670 596.000 930.950 600.000 ;
    END
  END sba_tl_h_o[104]
  PIN sba_tl_h_o[105]
    DIRECTION OUTPUT ;
    USE SIGNAL ;
    PORT
      LAYER met2 ;
        RECT 669.850 596.000 670.130 600.000 ;
    END
  END sba_tl_h_o[105]
  PIN sba_tl_h_o[106]
    DIRECTION OUTPUT ;
    USE SIGNAL ;
    ANTENNADIFFAREA 0.445500 ;
    PORT
      LAYER met2 ;
        RECT 515.290 0.000 515.570 4.000 ;
    END
  END sba_tl_h_o[106]
  PIN sba_tl_h_o[107]
    DIRECTION OUTPUT ;
    USE SIGNAL ;
    PORT
      LAYER met2 ;
        RECT 415.470 0.000 415.750 4.000 ;
    END
  END sba_tl_h_o[107]
  PIN sba_tl_h_o[108]
    DIRECTION OUTPUT ;
    USE SIGNAL ;
    ANTENNADIFFAREA 0.445500 ;
    PORT
      LAYER met2 ;
        RECT 524.950 0.000 525.230 4.000 ;
    END
  END sba_tl_h_o[108]
  PIN sba_tl_h_o[109]
    DIRECTION OUTPUT ;
    USE SIGNAL ;
    ANTENNADIFFAREA 0.445500 ;
    PORT
      LAYER met2 ;
        RECT 579.690 0.000 579.970 4.000 ;
    END
  END sba_tl_h_o[109]
  PIN sba_tl_h_o[10]
    DIRECTION OUTPUT ;
    USE SIGNAL ;
    ANTENNADIFFAREA 0.445500 ;
    PORT
      LAYER met2 ;
        RECT 505.630 0.000 505.910 4.000 ;
    END
  END sba_tl_h_o[10]
  PIN sba_tl_h_o[11]
    DIRECTION OUTPUT ;
    USE SIGNAL ;
    ANTENNADIFFAREA 0.445500 ;
    PORT
      LAYER met2 ;
        RECT 434.790 0.000 435.070 4.000 ;
    END
  END sba_tl_h_o[11]
  PIN sba_tl_h_o[12]
    DIRECTION OUTPUT ;
    USE SIGNAL ;
    ANTENNADIFFAREA 0.445500 ;
    PORT
      LAYER met2 ;
        RECT 466.990 0.000 467.270 4.000 ;
    END
  END sba_tl_h_o[12]
  PIN sba_tl_h_o[13]
    DIRECTION OUTPUT ;
    USE SIGNAL ;
    ANTENNADIFFAREA 0.445500 ;
    PORT
      LAYER met2 ;
        RECT 418.690 0.000 418.970 4.000 ;
    END
  END sba_tl_h_o[13]
  PIN sba_tl_h_o[14]
    DIRECTION OUTPUT ;
    USE SIGNAL ;
    ANTENNADIFFAREA 0.445500 ;
    PORT
      LAYER met2 ;
        RECT 476.650 0.000 476.930 4.000 ;
    END
  END sba_tl_h_o[14]
  PIN sba_tl_h_o[15]
    DIRECTION OUTPUT ;
    USE SIGNAL ;
    PORT
      LAYER met2 ;
        RECT 438.010 0.000 438.290 4.000 ;
    END
  END sba_tl_h_o[15]
  PIN sba_tl_h_o[16]
    DIRECTION OUTPUT ;
    USE SIGNAL ;
    PORT
      LAYER met2 ;
        RECT 9.750 596.000 10.030 600.000 ;
    END
  END sba_tl_h_o[16]
  PIN sba_tl_h_o[17]
    DIRECTION OUTPUT ;
    USE SIGNAL ;
    PORT
      LAYER met2 ;
        RECT 1088.450 596.000 1088.730 600.000 ;
    END
  END sba_tl_h_o[17]
  PIN sba_tl_h_o[18]
    DIRECTION OUTPUT ;
    USE SIGNAL ;
    PORT
      LAYER met2 ;
        RECT 602.230 0.000 602.510 4.000 ;
    END
  END sba_tl_h_o[18]
  PIN sba_tl_h_o[19]
    DIRECTION OUTPUT ;
    USE SIGNAL ;
    PORT
      LAYER met2 ;
        RECT 1072.350 596.000 1072.630 600.000 ;
    END
  END sba_tl_h_o[19]
  PIN sba_tl_h_o[1]
    DIRECTION OUTPUT ;
    USE SIGNAL ;
    ANTENNADIFFAREA 0.445500 ;
    PORT
      LAYER met2 ;
        RECT 869.490 0.000 869.770 4.000 ;
    END
  END sba_tl_h_o[1]
  PIN sba_tl_h_o[20]
    DIRECTION OUTPUT ;
    USE SIGNAL ;
    PORT
      LAYER met2 ;
        RECT 338.190 0.000 338.470 4.000 ;
    END
  END sba_tl_h_o[20]
  PIN sba_tl_h_o[21]
    DIRECTION OUTPUT ;
    USE SIGNAL ;
    PORT
      LAYER met2 ;
        RECT 1053.030 596.000 1053.310 600.000 ;
    END
  END sba_tl_h_o[21]
  PIN sba_tl_h_o[22]
    DIRECTION OUTPUT ;
    USE SIGNAL ;
    PORT
      LAYER met2 ;
        RECT 1033.710 596.000 1033.990 600.000 ;
    END
  END sba_tl_h_o[22]
  PIN sba_tl_h_o[23]
    DIRECTION OUTPUT ;
    USE SIGNAL ;
    PORT
      LAYER met2 ;
        RECT 608.670 596.000 608.950 600.000 ;
    END
  END sba_tl_h_o[23]
  PIN sba_tl_h_o[24]
    DIRECTION OUTPUT ;
    USE SIGNAL ;
    PORT
      LAYER met2 ;
        RECT 470.210 0.000 470.490 4.000 ;
    END
  END sba_tl_h_o[24]
  PIN sba_tl_h_o[25]
    DIRECTION OUTPUT ;
    USE SIGNAL ;
    ANTENNADIFFAREA 0.445500 ;
    PORT
      LAYER met2 ;
        RECT 743.910 0.000 744.190 4.000 ;
    END
  END sba_tl_h_o[25]
  PIN sba_tl_h_o[26]
    DIRECTION OUTPUT ;
    USE SIGNAL ;
    ANTENNADIFFAREA 0.445500 ;
    PORT
      LAYER met2 ;
        RECT 779.330 0.000 779.610 4.000 ;
    END
  END sba_tl_h_o[26]
  PIN sba_tl_h_o[27]
    DIRECTION OUTPUT ;
    USE SIGNAL ;
    ANTENNADIFFAREA 0.445500 ;
    PORT
      LAYER met2 ;
        RECT 853.390 0.000 853.670 4.000 ;
    END
  END sba_tl_h_o[27]
  PIN sba_tl_h_o[28]
    DIRECTION OUTPUT ;
    USE SIGNAL ;
    ANTENNADIFFAREA 0.445500 ;
    PORT
      LAYER met2 ;
        RECT 875.930 0.000 876.210 4.000 ;
    END
  END sba_tl_h_o[28]
  PIN sba_tl_h_o[29]
    DIRECTION OUTPUT ;
    USE SIGNAL ;
    ANTENNADIFFAREA 0.445500 ;
    PORT
      LAYER met2 ;
        RECT 721.370 0.000 721.650 4.000 ;
    END
  END sba_tl_h_o[29]
  PIN sba_tl_h_o[2]
    DIRECTION OUTPUT ;
    USE SIGNAL ;
    ANTENNADIFFAREA 0.445500 ;
    PORT
      LAYER met2 ;
        RECT 930.670 0.000 930.950 4.000 ;
    END
  END sba_tl_h_o[2]
  PIN sba_tl_h_o[30]
    DIRECTION OUTPUT ;
    USE SIGNAL ;
    ANTENNADIFFAREA 0.445500 ;
    PORT
      LAYER met2 ;
        RECT 763.230 0.000 763.510 4.000 ;
    END
  END sba_tl_h_o[30]
  PIN sba_tl_h_o[31]
    DIRECTION OUTPUT ;
    USE SIGNAL ;
    ANTENNADIFFAREA 0.445500 ;
    PORT
      LAYER met2 ;
        RECT 772.890 0.000 773.170 4.000 ;
    END
  END sba_tl_h_o[31]
  PIN sba_tl_h_o[32]
    DIRECTION OUTPUT ;
    USE SIGNAL ;
    ANTENNADIFFAREA 0.445500 ;
    PORT
      LAYER met2 ;
        RECT 908.130 0.000 908.410 4.000 ;
    END
  END sba_tl_h_o[32]
  PIN sba_tl_h_o[33]
    DIRECTION OUTPUT ;
    USE SIGNAL ;
    ANTENNADIFFAREA 0.445500 ;
    PORT
      LAYER met2 ;
        RECT 685.950 0.000 686.230 4.000 ;
    END
  END sba_tl_h_o[33]
  PIN sba_tl_h_o[34]
    DIRECTION OUTPUT ;
    USE SIGNAL ;
    ANTENNADIFFAREA 0.445500 ;
    PORT
      LAYER met2 ;
        RECT 840.510 0.000 840.790 4.000 ;
    END
  END sba_tl_h_o[34]
  PIN sba_tl_h_o[35]
    DIRECTION OUTPUT ;
    USE SIGNAL ;
    ANTENNADIFFAREA 0.445500 ;
    PORT
      LAYER met2 ;
        RECT 821.190 0.000 821.470 4.000 ;
    END
  END sba_tl_h_o[35]
  PIN sba_tl_h_o[36]
    DIRECTION OUTPUT ;
    USE SIGNAL ;
    ANTENNADIFFAREA 0.445500 ;
    PORT
      LAYER met2 ;
        RECT 811.530 0.000 811.810 4.000 ;
    END
  END sba_tl_h_o[36]
  PIN sba_tl_h_o[37]
    DIRECTION OUTPUT ;
    USE SIGNAL ;
    ANTENNADIFFAREA 0.445500 ;
    PORT
      LAYER met2 ;
        RECT 766.450 0.000 766.730 4.000 ;
    END
  END sba_tl_h_o[37]
  PIN sba_tl_h_o[38]
    DIRECTION OUTPUT ;
    USE SIGNAL ;
    ANTENNADIFFAREA 0.445500 ;
    PORT
      LAYER met2 ;
        RECT 698.830 0.000 699.110 4.000 ;
    END
  END sba_tl_h_o[38]
  PIN sba_tl_h_o[39]
    DIRECTION OUTPUT ;
    USE SIGNAL ;
    ANTENNADIFFAREA 0.445500 ;
    PORT
      LAYER met2 ;
        RECT 892.030 0.000 892.310 4.000 ;
    END
  END sba_tl_h_o[39]
  PIN sba_tl_h_o[3]
    DIRECTION OUTPUT ;
    USE SIGNAL ;
    ANTENNADIFFAREA 0.445500 ;
    PORT
      LAYER met2 ;
        RECT 927.450 0.000 927.730 4.000 ;
    END
  END sba_tl_h_o[3]
  PIN sba_tl_h_o[40]
    DIRECTION OUTPUT ;
    USE SIGNAL ;
    ANTENNADIFFAREA 0.445500 ;
    PORT
      LAYER met2 ;
        RECT 731.030 0.000 731.310 4.000 ;
    END
  END sba_tl_h_o[40]
  PIN sba_tl_h_o[41]
    DIRECTION OUTPUT ;
    USE SIGNAL ;
    ANTENNADIFFAREA 0.445500 ;
    PORT
      LAYER met2 ;
        RECT 859.830 0.000 860.110 4.000 ;
    END
  END sba_tl_h_o[41]
  PIN sba_tl_h_o[42]
    DIRECTION OUTPUT ;
    USE SIGNAL ;
    ANTENNADIFFAREA 0.445500 ;
    PORT
      LAYER met2 ;
        RECT 795.430 0.000 795.710 4.000 ;
    END
  END sba_tl_h_o[42]
  PIN sba_tl_h_o[43]
    DIRECTION OUTPUT ;
    USE SIGNAL ;
    ANTENNADIFFAREA 0.445500 ;
    PORT
      LAYER met2 ;
        RECT 850.170 0.000 850.450 4.000 ;
    END
  END sba_tl_h_o[43]
  PIN sba_tl_h_o[44]
    DIRECTION OUTPUT ;
    USE SIGNAL ;
    ANTENNADIFFAREA 0.445500 ;
    PORT
      LAYER met2 ;
        RECT 808.310 0.000 808.590 4.000 ;
    END
  END sba_tl_h_o[44]
  PIN sba_tl_h_o[45]
    DIRECTION OUTPUT ;
    USE SIGNAL ;
    ANTENNADIFFAREA 0.445500 ;
    PORT
      LAYER met2 ;
        RECT 785.770 0.000 786.050 4.000 ;
    END
  END sba_tl_h_o[45]
  PIN sba_tl_h_o[46]
    DIRECTION OUTPUT ;
    USE SIGNAL ;
    ANTENNADIFFAREA 0.445500 ;
    PORT
      LAYER met2 ;
        RECT 824.410 0.000 824.690 4.000 ;
    END
  END sba_tl_h_o[46]
  PIN sba_tl_h_o[47]
    DIRECTION OUTPUT ;
    USE SIGNAL ;
    ANTENNADIFFAREA 0.445500 ;
    PORT
      LAYER met2 ;
        RECT 863.050 0.000 863.330 4.000 ;
    END
  END sba_tl_h_o[47]
  PIN sba_tl_h_o[48]
    DIRECTION OUTPUT ;
    USE SIGNAL ;
    ANTENNADIFFAREA 0.445500 ;
    PORT
      LAYER met2 ;
        RECT 747.130 0.000 747.410 4.000 ;
    END
  END sba_tl_h_o[48]
  PIN sba_tl_h_o[49]
    DIRECTION OUTPUT ;
    USE SIGNAL ;
    ANTENNADIFFAREA 0.445500 ;
    PORT
      LAYER met2 ;
        RECT 837.290 0.000 837.570 4.000 ;
    END
  END sba_tl_h_o[49]
  PIN sba_tl_h_o[4]
    DIRECTION OUTPUT ;
    USE SIGNAL ;
    ANTENNADIFFAREA 0.445500 ;
    PORT
      LAYER met2 ;
        RECT 750.350 0.000 750.630 4.000 ;
    END
  END sba_tl_h_o[4]
  PIN sba_tl_h_o[50]
    DIRECTION OUTPUT ;
    USE SIGNAL ;
    ANTENNADIFFAREA 0.445500 ;
    PORT
      LAYER met2 ;
        RECT 830.850 0.000 831.130 4.000 ;
    END
  END sba_tl_h_o[50]
  PIN sba_tl_h_o[51]
    DIRECTION OUTPUT ;
    USE SIGNAL ;
    ANTENNADIFFAREA 0.445500 ;
    PORT
      LAYER met2 ;
        RECT 904.910 0.000 905.190 4.000 ;
    END
  END sba_tl_h_o[51]
  PIN sba_tl_h_o[52]
    DIRECTION OUTPUT ;
    USE SIGNAL ;
    ANTENNADIFFAREA 0.445500 ;
    PORT
      LAYER met2 ;
        RECT 901.690 0.000 901.970 4.000 ;
    END
  END sba_tl_h_o[52]
  PIN sba_tl_h_o[53]
    DIRECTION OUTPUT ;
    USE SIGNAL ;
    ANTENNADIFFAREA 0.445500 ;
    PORT
      LAYER met2 ;
        RECT 885.590 0.000 885.870 4.000 ;
    END
  END sba_tl_h_o[53]
  PIN sba_tl_h_o[54]
    DIRECTION OUTPUT ;
    USE SIGNAL ;
    ANTENNADIFFAREA 0.445500 ;
    PORT
      LAYER met2 ;
        RECT 782.550 0.000 782.830 4.000 ;
    END
  END sba_tl_h_o[54]
  PIN sba_tl_h_o[55]
    DIRECTION OUTPUT ;
    USE SIGNAL ;
    ANTENNADIFFAREA 0.445500 ;
    PORT
      LAYER met2 ;
        RECT 879.150 0.000 879.430 4.000 ;
    END
  END sba_tl_h_o[55]
  PIN sba_tl_h_o[56]
    DIRECTION OUTPUT ;
    USE SIGNAL ;
    ANTENNADIFFAREA 0.445500 ;
    PORT
      LAYER met2 ;
        RECT 798.650 0.000 798.930 4.000 ;
    END
  END sba_tl_h_o[56]
  PIN sba_tl_h_o[57]
    DIRECTION OUTPUT ;
    USE SIGNAL ;
    ANTENNADIFFAREA 0.445500 ;
    PORT
      LAYER met2 ;
        RECT 566.810 0.000 567.090 4.000 ;
    END
  END sba_tl_h_o[57]
  PIN sba_tl_h_o[58]
    DIRECTION OUTPUT ;
    USE SIGNAL ;
    ANTENNADIFFAREA 0.445500 ;
    PORT
      LAYER met2 ;
        RECT 557.150 0.000 557.430 4.000 ;
    END
  END sba_tl_h_o[58]
  PIN sba_tl_h_o[59]
    DIRECTION OUTPUT ;
    USE SIGNAL ;
    ANTENNADIFFAREA 0.445500 ;
    PORT
      LAYER met2 ;
        RECT 570.030 0.000 570.310 4.000 ;
    END
  END sba_tl_h_o[59]
  PIN sba_tl_h_o[5]
    DIRECTION OUTPUT ;
    USE SIGNAL ;
    ANTENNADIFFAREA 0.445500 ;
    PORT
      LAYER met2 ;
        RECT 740.690 0.000 740.970 4.000 ;
    END
  END sba_tl_h_o[5]
  PIN sba_tl_h_o[60]
    DIRECTION OUTPUT ;
    USE SIGNAL ;
    ANTENNADIFFAREA 0.445500 ;
    PORT
      LAYER met2 ;
        RECT 563.590 0.000 563.870 4.000 ;
    END
  END sba_tl_h_o[60]
  PIN sba_tl_h_o[61]
    DIRECTION OUTPUT ;
    USE SIGNAL ;
    ANTENNADIFFAREA 0.445500 ;
    PORT
      LAYER met2 ;
        RECT 544.270 0.000 544.550 4.000 ;
    END
  END sba_tl_h_o[61]
  PIN sba_tl_h_o[62]
    DIRECTION OUTPUT ;
    USE SIGNAL ;
    ANTENNADIFFAREA 0.445500 ;
    PORT
      LAYER met2 ;
        RECT 486.310 0.000 486.590 4.000 ;
    END
  END sba_tl_h_o[62]
  PIN sba_tl_h_o[63]
    DIRECTION OUTPUT ;
    USE SIGNAL ;
    ANTENNADIFFAREA 0.445500 ;
    PORT
      LAYER met2 ;
        RECT 553.930 0.000 554.210 4.000 ;
    END
  END sba_tl_h_o[63]
  PIN sba_tl_h_o[64]
    DIRECTION OUTPUT ;
    USE SIGNAL ;
    ANTENNADIFFAREA 0.445500 ;
    PORT
      LAYER met2 ;
        RECT 541.050 0.000 541.330 4.000 ;
    END
  END sba_tl_h_o[64]
  PIN sba_tl_h_o[65]
    DIRECTION OUTPUT ;
    USE SIGNAL ;
    ANTENNADIFFAREA 0.445500 ;
    PORT
      LAYER met2 ;
        RECT 547.490 0.000 547.770 4.000 ;
    END
  END sba_tl_h_o[65]
  PIN sba_tl_h_o[66]
    DIRECTION OUTPUT ;
    USE SIGNAL ;
    ANTENNADIFFAREA 0.445500 ;
    PORT
      LAYER met2 ;
        RECT 560.370 0.000 560.650 4.000 ;
    END
  END sba_tl_h_o[66]
  PIN sba_tl_h_o[67]
    DIRECTION OUTPUT ;
    USE SIGNAL ;
    ANTENNADIFFAREA 0.445500 ;
    PORT
      LAYER met2 ;
        RECT 537.830 0.000 538.110 4.000 ;
    END
  END sba_tl_h_o[67]
  PIN sba_tl_h_o[68]
    DIRECTION OUTPUT ;
    USE SIGNAL ;
    ANTENNADIFFAREA 0.445500 ;
    PORT
      LAYER met2 ;
        RECT 550.710 0.000 550.990 4.000 ;
    END
  END sba_tl_h_o[68]
  PIN sba_tl_h_o[69]
    DIRECTION OUTPUT ;
    USE SIGNAL ;
    ANTENNADIFFAREA 0.445500 ;
    PORT
      LAYER met2 ;
        RECT 489.530 0.000 489.810 4.000 ;
    END
  END sba_tl_h_o[69]
  PIN sba_tl_h_o[6]
    DIRECTION OUTPUT ;
    USE SIGNAL ;
    ANTENNADIFFAREA 0.445500 ;
    PORT
      LAYER met2 ;
        RECT 866.270 0.000 866.550 4.000 ;
    END
  END sba_tl_h_o[6]
  PIN sba_tl_h_o[70]
    DIRECTION OUTPUT ;
    USE SIGNAL ;
    ANTENNADIFFAREA 0.445500 ;
    PORT
      LAYER met2 ;
        RECT 528.170 0.000 528.450 4.000 ;
    END
  END sba_tl_h_o[70]
  PIN sba_tl_h_o[71]
    DIRECTION OUTPUT ;
    USE SIGNAL ;
    ANTENNADIFFAREA 0.445500 ;
    PORT
      LAYER met2 ;
        RECT 508.850 0.000 509.130 4.000 ;
    END
  END sba_tl_h_o[71]
  PIN sba_tl_h_o[72]
    DIRECTION OUTPUT ;
    USE SIGNAL ;
    ANTENNADIFFAREA 0.445500 ;
    PORT
      LAYER met2 ;
        RECT 534.610 0.000 534.890 4.000 ;
    END
  END sba_tl_h_o[72]
  PIN sba_tl_h_o[73]
    DIRECTION OUTPUT ;
    USE SIGNAL ;
    ANTENNADIFFAREA 0.445500 ;
    PORT
      LAYER met2 ;
        RECT 492.750 0.000 493.030 4.000 ;
    END
  END sba_tl_h_o[73]
  PIN sba_tl_h_o[74]
    DIRECTION OUTPUT ;
    USE SIGNAL ;
    ANTENNADIFFAREA 0.445500 ;
    PORT
      LAYER met2 ;
        RECT 499.190 0.000 499.470 4.000 ;
    END
  END sba_tl_h_o[74]
  PIN sba_tl_h_o[75]
    DIRECTION OUTPUT ;
    USE SIGNAL ;
    ANTENNADIFFAREA 0.445500 ;
    PORT
      LAYER met2 ;
        RECT 502.410 0.000 502.690 4.000 ;
    END
  END sba_tl_h_o[75]
  PIN sba_tl_h_o[76]
    DIRECTION OUTPUT ;
    USE SIGNAL ;
    ANTENNADIFFAREA 0.445500 ;
    PORT
      LAYER met2 ;
        RECT 512.070 0.000 512.350 4.000 ;
    END
  END sba_tl_h_o[76]
  PIN sba_tl_h_o[77]
    DIRECTION OUTPUT ;
    USE SIGNAL ;
    ANTENNADIFFAREA 0.445500 ;
    PORT
      LAYER met2 ;
        RECT 518.510 0.000 518.790 4.000 ;
    END
  END sba_tl_h_o[77]
  PIN sba_tl_h_o[78]
    DIRECTION OUTPUT ;
    USE SIGNAL ;
    ANTENNADIFFAREA 0.445500 ;
    PORT
      LAYER met2 ;
        RECT 483.090 0.000 483.370 4.000 ;
    END
  END sba_tl_h_o[78]
  PIN sba_tl_h_o[79]
    DIRECTION OUTPUT ;
    USE SIGNAL ;
    ANTENNADIFFAREA 0.445500 ;
    PORT
      LAYER met2 ;
        RECT 473.430 0.000 473.710 4.000 ;
    END
  END sba_tl_h_o[79]
  PIN sba_tl_h_o[7]
    DIRECTION OUTPUT ;
    USE SIGNAL ;
    ANTENNADIFFAREA 0.445500 ;
    PORT
      LAYER met2 ;
        RECT 788.990 0.000 789.270 4.000 ;
    END
  END sba_tl_h_o[7]
  PIN sba_tl_h_o[80]
    DIRECTION OUTPUT ;
    USE SIGNAL ;
    ANTENNADIFFAREA 0.445500 ;
    PORT
      LAYER met2 ;
        RECT 431.570 0.000 431.850 4.000 ;
    END
  END sba_tl_h_o[80]
  PIN sba_tl_h_o[81]
    DIRECTION OUTPUT ;
    USE SIGNAL ;
    ANTENNADIFFAREA 0.445500 ;
    PORT
      LAYER met2 ;
        RECT 428.350 0.000 428.630 4.000 ;
    END
  END sba_tl_h_o[81]
  PIN sba_tl_h_o[82]
    DIRECTION OUTPUT ;
    USE SIGNAL ;
    ANTENNADIFFAREA 0.445500 ;
    PORT
      LAYER met2 ;
        RECT 479.870 0.000 480.150 4.000 ;
    END
  END sba_tl_h_o[82]
  PIN sba_tl_h_o[83]
    DIRECTION OUTPUT ;
    USE SIGNAL ;
    ANTENNADIFFAREA 0.445500 ;
    PORT
      LAYER met2 ;
        RECT 463.770 0.000 464.050 4.000 ;
    END
  END sba_tl_h_o[83]
  PIN sba_tl_h_o[84]
    DIRECTION OUTPUT ;
    USE SIGNAL ;
    ANTENNADIFFAREA 0.445500 ;
    PORT
      LAYER met2 ;
        RECT 421.910 0.000 422.190 4.000 ;
    END
  END sba_tl_h_o[84]
  PIN sba_tl_h_o[85]
    DIRECTION OUTPUT ;
    USE SIGNAL ;
    ANTENNADIFFAREA 0.445500 ;
    PORT
      LAYER met2 ;
        RECT 425.130 0.000 425.410 4.000 ;
    END
  END sba_tl_h_o[85]
  PIN sba_tl_h_o[86]
    DIRECTION OUTPUT ;
    USE SIGNAL ;
    ANTENNADIFFAREA 0.445500 ;
    PORT
      LAYER met2 ;
        RECT 441.230 0.000 441.510 4.000 ;
    END
  END sba_tl_h_o[86]
  PIN sba_tl_h_o[87]
    DIRECTION OUTPUT ;
    USE SIGNAL ;
    ANTENNADIFFAREA 0.445500 ;
    PORT
      LAYER met2 ;
        RECT 457.330 0.000 457.610 4.000 ;
    END
  END sba_tl_h_o[87]
  PIN sba_tl_h_o[88]
    DIRECTION OUTPUT ;
    USE SIGNAL ;
    ANTENNADIFFAREA 0.445500 ;
    PORT
      LAYER met2 ;
        RECT 447.670 0.000 447.950 4.000 ;
    END
  END sba_tl_h_o[88]
  PIN sba_tl_h_o[89]
    DIRECTION OUTPUT ;
    USE SIGNAL ;
    ANTENNADIFFAREA 0.445500 ;
    PORT
      LAYER met2 ;
        RECT 454.110 0.000 454.390 4.000 ;
    END
  END sba_tl_h_o[89]
  PIN sba_tl_h_o[8]
    DIRECTION OUTPUT ;
    USE SIGNAL ;
    ANTENNADIFFAREA 0.445500 ;
    PORT
      LAYER met2 ;
        RECT 531.390 0.000 531.670 4.000 ;
    END
  END sba_tl_h_o[8]
  PIN sba_tl_h_o[90]
    DIRECTION OUTPUT ;
    USE SIGNAL ;
    ANTENNADIFFAREA 0.445500 ;
    PORT
      LAYER met2 ;
        RECT 450.890 0.000 451.170 4.000 ;
    END
  END sba_tl_h_o[90]
  PIN sba_tl_h_o[91]
    DIRECTION OUTPUT ;
    USE SIGNAL ;
    ANTENNADIFFAREA 0.445500 ;
    PORT
      LAYER met2 ;
        RECT 444.450 0.000 444.730 4.000 ;
    END
  END sba_tl_h_o[91]
  PIN sba_tl_h_o[92]
    DIRECTION OUTPUT ;
    USE SIGNAL ;
    ANTENNADIFFAREA 0.445500 ;
    PORT
      LAYER met2 ;
        RECT 460.550 0.000 460.830 4.000 ;
    END
  END sba_tl_h_o[92]
  PIN sba_tl_h_o[93]
    DIRECTION OUTPUT ;
    USE SIGNAL ;
    PORT
      LAYER met2 ;
        RECT 731.030 596.000 731.310 600.000 ;
    END
  END sba_tl_h_o[93]
  PIN sba_tl_h_o[94]
    DIRECTION OUTPUT ;
    USE SIGNAL ;
    PORT
      LAYER met2 ;
        RECT 1082.010 0.000 1082.290 4.000 ;
    END
  END sba_tl_h_o[94]
  PIN sba_tl_h_o[95]
    DIRECTION OUTPUT ;
    USE SIGNAL ;
    PORT
      LAYER met2 ;
        RECT 914.570 596.000 914.850 600.000 ;
    END
  END sba_tl_h_o[95]
  PIN sba_tl_h_o[96]
    DIRECTION OUTPUT ;
    USE SIGNAL ;
    PORT
      LAYER met2 ;
        RECT 792.210 596.000 792.490 600.000 ;
    END
  END sba_tl_h_o[96]
  PIN sba_tl_h_o[97]
    DIRECTION OUTPUT ;
    USE SIGNAL ;
    PORT
      LAYER met2 ;
        RECT 409.030 0.000 409.310 4.000 ;
    END
  END sba_tl_h_o[97]
  PIN sba_tl_h_o[98]
    DIRECTION OUTPUT ;
    USE SIGNAL ;
    PORT
      LAYER met2 ;
        RECT 650.530 0.000 650.810 4.000 ;
    END
  END sba_tl_h_o[98]
  PIN sba_tl_h_o[99]
    DIRECTION OUTPUT ;
    USE SIGNAL ;
    PORT
      LAYER met2 ;
        RECT 495.970 0.000 496.250 4.000 ;
    END
  END sba_tl_h_o[99]
  PIN sba_tl_h_o[9]
    DIRECTION OUTPUT ;
    USE SIGNAL ;
    ANTENNADIFFAREA 0.445500 ;
    PORT
      LAYER met2 ;
        RECT 521.730 0.000 522.010 4.000 ;
    END
  END sba_tl_h_o[9]
  PIN testmode_i
    DIRECTION INPUT ;
    USE SIGNAL ;
    ANTENNAGATEAREA 0.631200 ;
    ANTENNADIFFAREA 0.434700 ;
    PORT
      LAYER met2 ;
        RECT 357.510 596.000 357.790 600.000 ;
    END
  END testmode_i
  PIN unavailable_i
    DIRECTION INPUT ;
    USE SIGNAL ;
    ANTENNAGATEAREA 0.593700 ;
    ANTENNADIFFAREA 0.434700 ;
    PORT
      LAYER met2 ;
        RECT 817.970 0.000 818.250 4.000 ;
    END
  END unavailable_i
  OBS
      LAYER nwell ;
        RECT 5.330 10.760 1294.630 587.640 ;
      LAYER li1 ;
        RECT 5.520 10.795 1294.440 587.605 ;
      LAYER met1 ;
        RECT 5.520 6.160 1294.440 596.660 ;
      LAYER met2 ;
        RECT 10.310 595.720 341.130 597.450 ;
        RECT 341.970 595.720 357.230 597.450 ;
        RECT 358.070 595.720 366.890 597.450 ;
        RECT 367.730 595.720 370.110 597.450 ;
        RECT 370.950 595.720 405.530 597.450 ;
        RECT 406.370 595.720 566.530 597.450 ;
        RECT 567.370 595.720 589.070 597.450 ;
        RECT 589.910 595.720 598.730 597.450 ;
        RECT 599.570 595.720 601.950 597.450 ;
        RECT 602.790 595.720 605.170 597.450 ;
        RECT 606.010 595.720 608.390 597.450 ;
        RECT 609.230 595.720 627.710 597.450 ;
        RECT 628.550 595.720 630.930 597.450 ;
        RECT 631.770 595.720 634.150 597.450 ;
        RECT 634.990 595.720 637.370 597.450 ;
        RECT 638.210 595.720 640.590 597.450 ;
        RECT 641.430 595.720 643.810 597.450 ;
        RECT 644.650 595.720 647.030 597.450 ;
        RECT 647.870 595.720 650.250 597.450 ;
        RECT 651.090 595.720 653.470 597.450 ;
        RECT 654.310 595.720 656.690 597.450 ;
        RECT 657.530 595.720 659.910 597.450 ;
        RECT 660.750 595.720 663.130 597.450 ;
        RECT 663.970 595.720 666.350 597.450 ;
        RECT 667.190 595.720 669.570 597.450 ;
        RECT 670.410 595.720 672.790 597.450 ;
        RECT 673.630 595.720 676.010 597.450 ;
        RECT 676.850 595.720 679.230 597.450 ;
        RECT 680.070 595.720 682.450 597.450 ;
        RECT 683.290 595.720 685.670 597.450 ;
        RECT 686.510 595.720 688.890 597.450 ;
        RECT 689.730 595.720 692.110 597.450 ;
        RECT 692.950 595.720 695.330 597.450 ;
        RECT 696.170 595.720 698.550 597.450 ;
        RECT 699.390 595.720 701.770 597.450 ;
        RECT 702.610 595.720 704.990 597.450 ;
        RECT 705.830 595.720 708.210 597.450 ;
        RECT 709.050 595.720 711.430 597.450 ;
        RECT 712.270 595.720 714.650 597.450 ;
        RECT 715.490 595.720 717.870 597.450 ;
        RECT 718.710 595.720 721.090 597.450 ;
        RECT 721.930 595.720 724.310 597.450 ;
        RECT 725.150 595.720 727.530 597.450 ;
        RECT 728.370 595.720 730.750 597.450 ;
        RECT 731.590 595.720 733.970 597.450 ;
        RECT 734.810 595.720 737.190 597.450 ;
        RECT 738.030 595.720 740.410 597.450 ;
        RECT 741.250 595.720 743.630 597.450 ;
        RECT 744.470 595.720 746.850 597.450 ;
        RECT 747.690 595.720 750.070 597.450 ;
        RECT 750.910 595.720 753.290 597.450 ;
        RECT 754.130 595.720 756.510 597.450 ;
        RECT 757.350 595.720 759.730 597.450 ;
        RECT 760.570 595.720 762.950 597.450 ;
        RECT 763.790 595.720 766.170 597.450 ;
        RECT 767.010 595.720 769.390 597.450 ;
        RECT 770.230 595.720 772.610 597.450 ;
        RECT 773.450 595.720 775.830 597.450 ;
        RECT 776.670 595.720 779.050 597.450 ;
        RECT 779.890 595.720 782.270 597.450 ;
        RECT 783.110 595.720 785.490 597.450 ;
        RECT 786.330 595.720 788.710 597.450 ;
        RECT 789.550 595.720 791.930 597.450 ;
        RECT 792.770 595.720 795.150 597.450 ;
        RECT 795.990 595.720 798.370 597.450 ;
        RECT 799.210 595.720 801.590 597.450 ;
        RECT 802.430 595.720 804.810 597.450 ;
        RECT 805.650 595.720 808.030 597.450 ;
        RECT 808.870 595.720 811.250 597.450 ;
        RECT 812.090 595.720 814.470 597.450 ;
        RECT 815.310 595.720 817.690 597.450 ;
        RECT 818.530 595.720 820.910 597.450 ;
        RECT 821.750 595.720 824.130 597.450 ;
        RECT 824.970 595.720 827.350 597.450 ;
        RECT 828.190 595.720 830.570 597.450 ;
        RECT 831.410 595.720 833.790 597.450 ;
        RECT 834.630 595.720 837.010 597.450 ;
        RECT 837.850 595.720 840.230 597.450 ;
        RECT 841.070 595.720 843.450 597.450 ;
        RECT 844.290 595.720 846.670 597.450 ;
        RECT 847.510 595.720 849.890 597.450 ;
        RECT 850.730 595.720 853.110 597.450 ;
        RECT 853.950 595.720 856.330 597.450 ;
        RECT 857.170 595.720 859.550 597.450 ;
        RECT 860.390 595.720 862.770 597.450 ;
        RECT 863.610 595.720 865.990 597.450 ;
        RECT 866.830 595.720 869.210 597.450 ;
        RECT 870.050 595.720 872.430 597.450 ;
        RECT 873.270 595.720 875.650 597.450 ;
        RECT 876.490 595.720 878.870 597.450 ;
        RECT 879.710 595.720 882.090 597.450 ;
        RECT 882.930 595.720 885.310 597.450 ;
        RECT 886.150 595.720 888.530 597.450 ;
        RECT 889.370 595.720 891.750 597.450 ;
        RECT 892.590 595.720 894.970 597.450 ;
        RECT 895.810 595.720 898.190 597.450 ;
        RECT 899.030 595.720 901.410 597.450 ;
        RECT 902.250 595.720 904.630 597.450 ;
        RECT 905.470 595.720 907.850 597.450 ;
        RECT 908.690 595.720 911.070 597.450 ;
        RECT 911.910 595.720 914.290 597.450 ;
        RECT 915.130 595.720 917.510 597.450 ;
        RECT 918.350 595.720 920.730 597.450 ;
        RECT 921.570 595.720 923.950 597.450 ;
        RECT 924.790 595.720 927.170 597.450 ;
        RECT 928.010 595.720 930.390 597.450 ;
        RECT 931.230 595.720 933.610 597.450 ;
        RECT 934.450 595.720 936.830 597.450 ;
        RECT 937.670 595.720 940.050 597.450 ;
        RECT 940.890 595.720 943.270 597.450 ;
        RECT 944.110 595.720 946.490 597.450 ;
        RECT 947.330 595.720 949.710 597.450 ;
        RECT 950.550 595.720 952.930 597.450 ;
        RECT 953.770 595.720 956.150 597.450 ;
        RECT 956.990 595.720 959.370 597.450 ;
        RECT 960.210 595.720 962.590 597.450 ;
        RECT 963.430 595.720 965.810 597.450 ;
        RECT 966.650 595.720 969.030 597.450 ;
        RECT 969.870 595.720 972.250 597.450 ;
        RECT 973.090 595.720 975.470 597.450 ;
        RECT 976.310 595.720 978.690 597.450 ;
        RECT 979.530 595.720 981.910 597.450 ;
        RECT 982.750 595.720 985.130 597.450 ;
        RECT 985.970 595.720 988.350 597.450 ;
        RECT 989.190 595.720 991.570 597.450 ;
        RECT 992.410 595.720 994.790 597.450 ;
        RECT 995.630 595.720 998.010 597.450 ;
        RECT 998.850 595.720 1001.230 597.450 ;
        RECT 1002.070 595.720 1004.450 597.450 ;
        RECT 1005.290 595.720 1007.670 597.450 ;
        RECT 1008.510 595.720 1010.890 597.450 ;
        RECT 1011.730 595.720 1014.110 597.450 ;
        RECT 1014.950 595.720 1017.330 597.450 ;
        RECT 1018.170 595.720 1020.550 597.450 ;
        RECT 1021.390 595.720 1023.770 597.450 ;
        RECT 1024.610 595.720 1026.990 597.450 ;
        RECT 1027.830 595.720 1030.210 597.450 ;
        RECT 1031.050 595.720 1033.430 597.450 ;
        RECT 1034.270 595.720 1036.650 597.450 ;
        RECT 1037.490 595.720 1039.870 597.450 ;
        RECT 1040.710 595.720 1043.090 597.450 ;
        RECT 1043.930 595.720 1046.310 597.450 ;
        RECT 1047.150 595.720 1052.750 597.450 ;
        RECT 1053.590 595.720 1072.070 597.450 ;
        RECT 1072.910 595.720 1088.170 597.450 ;
        RECT 1089.010 595.720 1292.510 597.450 ;
        RECT 10.030 4.280 1292.510 595.720 ;
        RECT 10.310 0.155 12.690 4.280 ;
        RECT 13.530 0.155 15.910 4.280 ;
        RECT 16.750 0.155 19.130 4.280 ;
        RECT 19.970 0.155 22.350 4.280 ;
        RECT 23.190 0.155 25.570 4.280 ;
        RECT 26.410 0.155 28.790 4.280 ;
        RECT 29.630 0.155 32.010 4.280 ;
        RECT 32.850 0.155 35.230 4.280 ;
        RECT 36.070 0.155 38.450 4.280 ;
        RECT 39.290 0.155 41.670 4.280 ;
        RECT 42.510 0.155 44.890 4.280 ;
        RECT 45.730 0.155 48.110 4.280 ;
        RECT 48.950 0.155 51.330 4.280 ;
        RECT 52.170 0.155 54.550 4.280 ;
        RECT 55.390 0.155 57.770 4.280 ;
        RECT 58.610 0.155 60.990 4.280 ;
        RECT 61.830 0.155 64.210 4.280 ;
        RECT 65.050 0.155 67.430 4.280 ;
        RECT 68.270 0.155 70.650 4.280 ;
        RECT 71.490 0.155 73.870 4.280 ;
        RECT 74.710 0.155 77.090 4.280 ;
        RECT 77.930 0.155 80.310 4.280 ;
        RECT 81.150 0.155 83.530 4.280 ;
        RECT 84.370 0.155 86.750 4.280 ;
        RECT 87.590 0.155 89.970 4.280 ;
        RECT 90.810 0.155 93.190 4.280 ;
        RECT 94.030 0.155 96.410 4.280 ;
        RECT 97.250 0.155 99.630 4.280 ;
        RECT 100.470 0.155 102.850 4.280 ;
        RECT 103.690 0.155 106.070 4.280 ;
        RECT 106.910 0.155 109.290 4.280 ;
        RECT 110.130 0.155 112.510 4.280 ;
        RECT 113.350 0.155 115.730 4.280 ;
        RECT 116.570 0.155 118.950 4.280 ;
        RECT 119.790 0.155 122.170 4.280 ;
        RECT 123.010 0.155 125.390 4.280 ;
        RECT 126.230 0.155 128.610 4.280 ;
        RECT 129.450 0.155 131.830 4.280 ;
        RECT 132.670 0.155 135.050 4.280 ;
        RECT 135.890 0.155 138.270 4.280 ;
        RECT 139.110 0.155 141.490 4.280 ;
        RECT 142.330 0.155 144.710 4.280 ;
        RECT 145.550 0.155 147.930 4.280 ;
        RECT 148.770 0.155 151.150 4.280 ;
        RECT 151.990 0.155 154.370 4.280 ;
        RECT 155.210 0.155 157.590 4.280 ;
        RECT 158.430 0.155 160.810 4.280 ;
        RECT 161.650 0.155 164.030 4.280 ;
        RECT 164.870 0.155 167.250 4.280 ;
        RECT 168.090 0.155 170.470 4.280 ;
        RECT 171.310 0.155 173.690 4.280 ;
        RECT 174.530 0.155 176.910 4.280 ;
        RECT 177.750 0.155 180.130 4.280 ;
        RECT 180.970 0.155 183.350 4.280 ;
        RECT 184.190 0.155 186.570 4.280 ;
        RECT 187.410 0.155 189.790 4.280 ;
        RECT 190.630 0.155 193.010 4.280 ;
        RECT 193.850 0.155 196.230 4.280 ;
        RECT 197.070 0.155 199.450 4.280 ;
        RECT 200.290 0.155 202.670 4.280 ;
        RECT 203.510 0.155 205.890 4.280 ;
        RECT 206.730 0.155 209.110 4.280 ;
        RECT 209.950 0.155 212.330 4.280 ;
        RECT 213.170 0.155 215.550 4.280 ;
        RECT 216.390 0.155 218.770 4.280 ;
        RECT 219.610 0.155 221.990 4.280 ;
        RECT 222.830 0.155 225.210 4.280 ;
        RECT 226.050 0.155 228.430 4.280 ;
        RECT 229.270 0.155 231.650 4.280 ;
        RECT 232.490 0.155 234.870 4.280 ;
        RECT 235.710 0.155 238.090 4.280 ;
        RECT 238.930 0.155 241.310 4.280 ;
        RECT 242.150 0.155 244.530 4.280 ;
        RECT 245.370 0.155 247.750 4.280 ;
        RECT 248.590 0.155 250.970 4.280 ;
        RECT 251.810 0.155 254.190 4.280 ;
        RECT 255.030 0.155 337.910 4.280 ;
        RECT 338.750 0.155 408.750 4.280 ;
        RECT 409.590 0.155 415.190 4.280 ;
        RECT 416.030 0.155 418.410 4.280 ;
        RECT 419.250 0.155 421.630 4.280 ;
        RECT 422.470 0.155 424.850 4.280 ;
        RECT 425.690 0.155 428.070 4.280 ;
        RECT 428.910 0.155 431.290 4.280 ;
        RECT 432.130 0.155 434.510 4.280 ;
        RECT 435.350 0.155 437.730 4.280 ;
        RECT 438.570 0.155 440.950 4.280 ;
        RECT 441.790 0.155 444.170 4.280 ;
        RECT 445.010 0.155 447.390 4.280 ;
        RECT 448.230 0.155 450.610 4.280 ;
        RECT 451.450 0.155 453.830 4.280 ;
        RECT 454.670 0.155 457.050 4.280 ;
        RECT 457.890 0.155 460.270 4.280 ;
        RECT 461.110 0.155 463.490 4.280 ;
        RECT 464.330 0.155 466.710 4.280 ;
        RECT 467.550 0.155 469.930 4.280 ;
        RECT 470.770 0.155 473.150 4.280 ;
        RECT 473.990 0.155 476.370 4.280 ;
        RECT 477.210 0.155 479.590 4.280 ;
        RECT 480.430 0.155 482.810 4.280 ;
        RECT 483.650 0.155 486.030 4.280 ;
        RECT 486.870 0.155 489.250 4.280 ;
        RECT 490.090 0.155 492.470 4.280 ;
        RECT 493.310 0.155 495.690 4.280 ;
        RECT 496.530 0.155 498.910 4.280 ;
        RECT 499.750 0.155 502.130 4.280 ;
        RECT 502.970 0.155 505.350 4.280 ;
        RECT 506.190 0.155 508.570 4.280 ;
        RECT 509.410 0.155 511.790 4.280 ;
        RECT 512.630 0.155 515.010 4.280 ;
        RECT 515.850 0.155 518.230 4.280 ;
        RECT 519.070 0.155 521.450 4.280 ;
        RECT 522.290 0.155 524.670 4.280 ;
        RECT 525.510 0.155 527.890 4.280 ;
        RECT 528.730 0.155 531.110 4.280 ;
        RECT 531.950 0.155 534.330 4.280 ;
        RECT 535.170 0.155 537.550 4.280 ;
        RECT 538.390 0.155 540.770 4.280 ;
        RECT 541.610 0.155 543.990 4.280 ;
        RECT 544.830 0.155 547.210 4.280 ;
        RECT 548.050 0.155 550.430 4.280 ;
        RECT 551.270 0.155 553.650 4.280 ;
        RECT 554.490 0.155 556.870 4.280 ;
        RECT 557.710 0.155 560.090 4.280 ;
        RECT 560.930 0.155 563.310 4.280 ;
        RECT 564.150 0.155 566.530 4.280 ;
        RECT 567.370 0.155 569.750 4.280 ;
        RECT 570.590 0.155 572.970 4.280 ;
        RECT 573.810 0.155 576.190 4.280 ;
        RECT 577.030 0.155 579.410 4.280 ;
        RECT 580.250 0.155 582.630 4.280 ;
        RECT 583.470 0.155 585.850 4.280 ;
        RECT 586.690 0.155 589.070 4.280 ;
        RECT 589.910 0.155 592.290 4.280 ;
        RECT 593.130 0.155 595.510 4.280 ;
        RECT 596.350 0.155 598.730 4.280 ;
        RECT 599.570 0.155 601.950 4.280 ;
        RECT 602.790 0.155 605.170 4.280 ;
        RECT 606.010 0.155 608.390 4.280 ;
        RECT 609.230 0.155 611.610 4.280 ;
        RECT 612.450 0.155 614.830 4.280 ;
        RECT 615.670 0.155 618.050 4.280 ;
        RECT 618.890 0.155 621.270 4.280 ;
        RECT 622.110 0.155 624.490 4.280 ;
        RECT 625.330 0.155 627.710 4.280 ;
        RECT 628.550 0.155 630.930 4.280 ;
        RECT 631.770 0.155 634.150 4.280 ;
        RECT 634.990 0.155 637.370 4.280 ;
        RECT 638.210 0.155 640.590 4.280 ;
        RECT 641.430 0.155 643.810 4.280 ;
        RECT 644.650 0.155 647.030 4.280 ;
        RECT 647.870 0.155 650.250 4.280 ;
        RECT 651.090 0.155 653.470 4.280 ;
        RECT 654.310 0.155 656.690 4.280 ;
        RECT 657.530 0.155 659.910 4.280 ;
        RECT 660.750 0.155 663.130 4.280 ;
        RECT 663.970 0.155 666.350 4.280 ;
        RECT 667.190 0.155 669.570 4.280 ;
        RECT 670.410 0.155 672.790 4.280 ;
        RECT 673.630 0.155 676.010 4.280 ;
        RECT 676.850 0.155 679.230 4.280 ;
        RECT 680.070 0.155 682.450 4.280 ;
        RECT 683.290 0.155 685.670 4.280 ;
        RECT 686.510 0.155 688.890 4.280 ;
        RECT 689.730 0.155 692.110 4.280 ;
        RECT 692.950 0.155 695.330 4.280 ;
        RECT 696.170 0.155 698.550 4.280 ;
        RECT 699.390 0.155 701.770 4.280 ;
        RECT 702.610 0.155 704.990 4.280 ;
        RECT 705.830 0.155 708.210 4.280 ;
        RECT 709.050 0.155 711.430 4.280 ;
        RECT 712.270 0.155 714.650 4.280 ;
        RECT 715.490 0.155 717.870 4.280 ;
        RECT 718.710 0.155 721.090 4.280 ;
        RECT 721.930 0.155 724.310 4.280 ;
        RECT 725.150 0.155 727.530 4.280 ;
        RECT 728.370 0.155 730.750 4.280 ;
        RECT 731.590 0.155 733.970 4.280 ;
        RECT 734.810 0.155 737.190 4.280 ;
        RECT 738.030 0.155 740.410 4.280 ;
        RECT 741.250 0.155 743.630 4.280 ;
        RECT 744.470 0.155 746.850 4.280 ;
        RECT 747.690 0.155 750.070 4.280 ;
        RECT 750.910 0.155 753.290 4.280 ;
        RECT 754.130 0.155 756.510 4.280 ;
        RECT 757.350 0.155 759.730 4.280 ;
        RECT 760.570 0.155 762.950 4.280 ;
        RECT 763.790 0.155 766.170 4.280 ;
        RECT 767.010 0.155 769.390 4.280 ;
        RECT 770.230 0.155 772.610 4.280 ;
        RECT 773.450 0.155 775.830 4.280 ;
        RECT 776.670 0.155 779.050 4.280 ;
        RECT 779.890 0.155 782.270 4.280 ;
        RECT 783.110 0.155 785.490 4.280 ;
        RECT 786.330 0.155 788.710 4.280 ;
        RECT 789.550 0.155 791.930 4.280 ;
        RECT 792.770 0.155 795.150 4.280 ;
        RECT 795.990 0.155 798.370 4.280 ;
        RECT 799.210 0.155 801.590 4.280 ;
        RECT 802.430 0.155 804.810 4.280 ;
        RECT 805.650 0.155 808.030 4.280 ;
        RECT 808.870 0.155 811.250 4.280 ;
        RECT 812.090 0.155 814.470 4.280 ;
        RECT 815.310 0.155 817.690 4.280 ;
        RECT 818.530 0.155 820.910 4.280 ;
        RECT 821.750 0.155 824.130 4.280 ;
        RECT 824.970 0.155 827.350 4.280 ;
        RECT 828.190 0.155 830.570 4.280 ;
        RECT 831.410 0.155 833.790 4.280 ;
        RECT 834.630 0.155 837.010 4.280 ;
        RECT 837.850 0.155 840.230 4.280 ;
        RECT 841.070 0.155 843.450 4.280 ;
        RECT 844.290 0.155 846.670 4.280 ;
        RECT 847.510 0.155 849.890 4.280 ;
        RECT 850.730 0.155 853.110 4.280 ;
        RECT 853.950 0.155 856.330 4.280 ;
        RECT 857.170 0.155 859.550 4.280 ;
        RECT 860.390 0.155 862.770 4.280 ;
        RECT 863.610 0.155 865.990 4.280 ;
        RECT 866.830 0.155 869.210 4.280 ;
        RECT 870.050 0.155 872.430 4.280 ;
        RECT 873.270 0.155 875.650 4.280 ;
        RECT 876.490 0.155 878.870 4.280 ;
        RECT 879.710 0.155 882.090 4.280 ;
        RECT 882.930 0.155 885.310 4.280 ;
        RECT 886.150 0.155 888.530 4.280 ;
        RECT 889.370 0.155 891.750 4.280 ;
        RECT 892.590 0.155 894.970 4.280 ;
        RECT 895.810 0.155 898.190 4.280 ;
        RECT 899.030 0.155 901.410 4.280 ;
        RECT 902.250 0.155 904.630 4.280 ;
        RECT 905.470 0.155 907.850 4.280 ;
        RECT 908.690 0.155 911.070 4.280 ;
        RECT 911.910 0.155 914.290 4.280 ;
        RECT 915.130 0.155 917.510 4.280 ;
        RECT 918.350 0.155 920.730 4.280 ;
        RECT 921.570 0.155 923.950 4.280 ;
        RECT 924.790 0.155 927.170 4.280 ;
        RECT 928.010 0.155 930.390 4.280 ;
        RECT 931.230 0.155 933.610 4.280 ;
        RECT 934.450 0.155 936.830 4.280 ;
        RECT 937.670 0.155 940.050 4.280 ;
        RECT 940.890 0.155 998.010 4.280 ;
        RECT 998.850 0.155 1007.670 4.280 ;
        RECT 1008.510 0.155 1081.730 4.280 ;
        RECT 1082.570 0.155 1292.510 4.280 ;
      LAYER met3 ;
        RECT 21.050 392.040 1296.000 596.865 ;
        RECT 21.050 390.640 1295.600 392.040 ;
        RECT 21.050 296.840 1296.000 390.640 ;
        RECT 21.050 295.440 1295.600 296.840 ;
        RECT 21.050 290.040 1296.000 295.440 ;
        RECT 21.050 288.640 1295.600 290.040 ;
        RECT 21.050 0.175 1296.000 288.640 ;
      LAYER met4 ;
        RECT 484.215 10.240 484.740 582.585 ;
        RECT 487.140 10.240 635.040 582.585 ;
        RECT 637.440 10.240 638.340 582.585 ;
        RECT 640.740 10.240 788.640 582.585 ;
        RECT 791.040 10.240 791.940 582.585 ;
        RECT 794.340 10.240 942.240 582.585 ;
        RECT 944.640 10.240 945.540 582.585 ;
        RECT 947.940 10.240 1000.650 582.585 ;
        RECT 484.215 0.175 1000.650 10.240 ;
  END
END vyges_rv_dbg_tlul
END LIBRARY

